VERSION 5.8 ;
BUSBITCHARS "[]" ;
DIVIDERCHAR "/" ;
UNITS
    DATABASE MICRONS 1000 ;
END UNITS

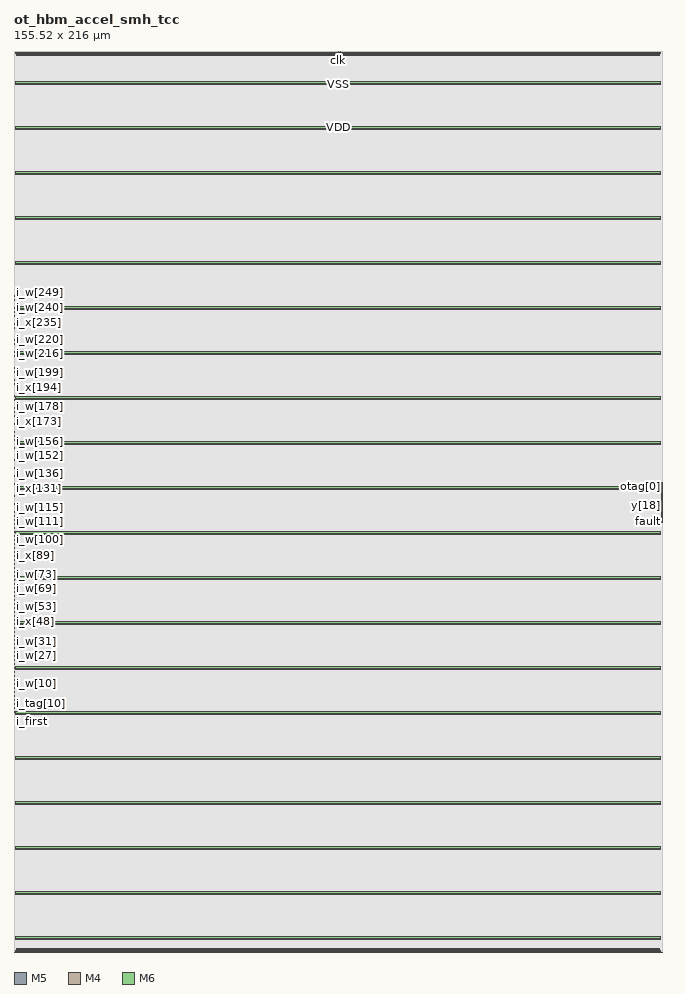
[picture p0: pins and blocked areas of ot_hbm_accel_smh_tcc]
MACRO ot_hbm_accel_smh_tcc
  FOREIGN ot_hbm_accel_smh_tcc 0 0 ;
  CLASS BLOCK ;
  SIZE 155.52 BY 216 ;
  PIN clk
    DIRECTION INPUT ;
    USE SIGNAL ;
    PORT
      LAYER M5 ;
        RECT  77.76 215.808 77.784 216 ;
    END
  END clk
  PIN fault
    DIRECTION OUTPUT ;
    USE SIGNAL ;
    PORT
      LAYER M4 ;
        RECT  155.328 103.392 155.52 103.416 ;
    END
  END fault
  PIN i_first
    DIRECTION INPUT ;
    USE SIGNAL ;
    PORT
      LAYER M4 ;
        RECT  0 57.216 0.192 57.24 ;
    END
  END i_first
  PIN i_last
    DIRECTION INPUT ;
    USE SIGNAL ;
    PORT
      LAYER M4 ;
        RECT  0 57.408 0.192 57.432 ;
    END
  END i_last
  PIN i_tag[0]
    DIRECTION INPUT ;
    USE SIGNAL ;
    PORT
      LAYER M4 ;
        RECT  0 57.6 0.192 57.624 ;
    END
  END i_tag[0]
  PIN i_tag[10]
    DIRECTION INPUT ;
    USE SIGNAL ;
    PORT
      LAYER M4 ;
        RECT  0 59.52 0.192 59.544 ;
    END
  END i_tag[10]
  PIN i_tag[11]
    DIRECTION INPUT ;
    USE SIGNAL ;
    PORT
      LAYER M4 ;
        RECT  0 59.712 0.192 59.736 ;
    END
  END i_tag[11]
  PIN i_tag[12]
    DIRECTION INPUT ;
    USE SIGNAL ;
    PORT
      LAYER M4 ;
        RECT  0 59.904 0.192 59.928 ;
    END
  END i_tag[12]
  PIN i_tag[13]
    DIRECTION INPUT ;
    USE SIGNAL ;
    PORT
      LAYER M4 ;
        RECT  0 60.096 0.192 60.12 ;
    END
  END i_tag[13]
  PIN i_tag[14]
    DIRECTION INPUT ;
    USE SIGNAL ;
    PORT
      LAYER M4 ;
        RECT  0 60.288 0.192 60.312 ;
    END
  END i_tag[14]
  PIN i_tag[15]
    DIRECTION INPUT ;
    USE SIGNAL ;
    PORT
      LAYER M4 ;
        RECT  0 60.48 0.192 60.504 ;
    END
  END i_tag[15]
  PIN i_tag[1]
    DIRECTION INPUT ;
    USE SIGNAL ;
    PORT
      LAYER M4 ;
        RECT  0 57.792 0.192 57.816 ;
    END
  END i_tag[1]
  PIN i_tag[2]
    DIRECTION INPUT ;
    USE SIGNAL ;
    PORT
      LAYER M4 ;
        RECT  0 57.984 0.192 58.008 ;
    END
  END i_tag[2]
  PIN i_tag[3]
    DIRECTION INPUT ;
    USE SIGNAL ;
    PORT
      LAYER M4 ;
        RECT  0 58.176 0.192 58.2 ;
    END
  END i_tag[3]
  PIN i_tag[4]
    DIRECTION INPUT ;
    USE SIGNAL ;
    PORT
      LAYER M4 ;
        RECT  0 58.368 0.192 58.392 ;
    END
  END i_tag[4]
  PIN i_tag[5]
    DIRECTION INPUT ;
    USE SIGNAL ;
    PORT
      LAYER M4 ;
        RECT  0 58.56 0.192 58.584 ;
    END
  END i_tag[5]
  PIN i_tag[6]
    DIRECTION INPUT ;
    USE SIGNAL ;
    PORT
      LAYER M4 ;
        RECT  0 58.752 0.192 58.776 ;
    END
  END i_tag[6]
  PIN i_tag[7]
    DIRECTION INPUT ;
    USE SIGNAL ;
    PORT
      LAYER M4 ;
        RECT  0 58.944 0.192 58.968 ;
    END
  END i_tag[7]
  PIN i_tag[8]
    DIRECTION INPUT ;
    USE SIGNAL ;
    PORT
      LAYER M4 ;
        RECT  0 59.136 0.192 59.16 ;
    END
  END i_tag[8]
  PIN i_tag[9]
    DIRECTION INPUT ;
    USE SIGNAL ;
    PORT
      LAYER M4 ;
        RECT  0 59.328 0.192 59.352 ;
    END
  END i_tag[9]
  PIN i_v
    DIRECTION INPUT ;
    USE SIGNAL ;
    PORT
      LAYER M4 ;
        RECT  0 57.024 0.192 57.048 ;
    END
  END i_v
  PIN i_w[0]
    DIRECTION INPUT ;
    USE SIGNAL ;
    PORT
      LAYER M4 ;
        RECT  0 60.672 0.192 60.696 ;
    END
  END i_w[0]
  PIN i_w[100]
    DIRECTION INPUT ;
    USE SIGNAL ;
    PORT
      LAYER M4 ;
        RECT  0 99.072 0.192 99.096 ;
    END
  END i_w[100]
  PIN i_w[101]
    DIRECTION INPUT ;
    USE SIGNAL ;
    PORT
      LAYER M4 ;
        RECT  0 99.456 0.192 99.48 ;
    END
  END i_w[101]
  PIN i_w[102]
    DIRECTION INPUT ;
    USE SIGNAL ;
    PORT
      LAYER M4 ;
        RECT  0 99.84 0.192 99.864 ;
    END
  END i_w[102]
  PIN i_w[103]
    DIRECTION INPUT ;
    USE SIGNAL ;
    PORT
      LAYER M4 ;
        RECT  0 100.224 0.192 100.248 ;
    END
  END i_w[103]
  PIN i_w[104]
    DIRECTION INPUT ;
    USE SIGNAL ;
    PORT
      LAYER M4 ;
        RECT  0 100.608 0.192 100.632 ;
    END
  END i_w[104]
  PIN i_w[105]
    DIRECTION INPUT ;
    USE SIGNAL ;
    PORT
      LAYER M4 ;
        RECT  0 100.992 0.192 101.016 ;
    END
  END i_w[105]
  PIN i_w[106]
    DIRECTION INPUT ;
    USE SIGNAL ;
    PORT
      LAYER M4 ;
        RECT  0 101.376 0.192 101.4 ;
    END
  END i_w[106]
  PIN i_w[107]
    DIRECTION INPUT ;
    USE SIGNAL ;
    PORT
      LAYER M4 ;
        RECT  0 101.76 0.192 101.784 ;
    END
  END i_w[107]
  PIN i_w[108]
    DIRECTION INPUT ;
    USE SIGNAL ;
    PORT
      LAYER M4 ;
        RECT  0 102.144 0.192 102.168 ;
    END
  END i_w[108]
  PIN i_w[109]
    DIRECTION INPUT ;
    USE SIGNAL ;
    PORT
      LAYER M4 ;
        RECT  0 102.528 0.192 102.552 ;
    END
  END i_w[109]
  PIN i_w[10]
    DIRECTION INPUT ;
    USE SIGNAL ;
    PORT
      LAYER M4 ;
        RECT  0 64.512 0.192 64.536 ;
    END
  END i_w[10]
  PIN i_w[110]
    DIRECTION INPUT ;
    USE SIGNAL ;
    PORT
      LAYER M4 ;
        RECT  0 102.912 0.192 102.936 ;
    END
  END i_w[110]
  PIN i_w[111]
    DIRECTION INPUT ;
    USE SIGNAL ;
    PORT
      LAYER M4 ;
        RECT  0 103.296 0.192 103.32 ;
    END
  END i_w[111]
  PIN i_w[112]
    DIRECTION INPUT ;
    USE SIGNAL ;
    PORT
      LAYER M4 ;
        RECT  0 103.68 0.192 103.704 ;
    END
  END i_w[112]
  PIN i_w[113]
    DIRECTION INPUT ;
    USE SIGNAL ;
    PORT
      LAYER M4 ;
        RECT  0 104.064 0.192 104.088 ;
    END
  END i_w[113]
  PIN i_w[114]
    DIRECTION INPUT ;
    USE SIGNAL ;
    PORT
      LAYER M4 ;
        RECT  0 104.448 0.192 104.472 ;
    END
  END i_w[114]
  PIN i_w[115]
    DIRECTION INPUT ;
    USE SIGNAL ;
    PORT
      LAYER M4 ;
        RECT  0 104.832 0.192 104.856 ;
    END
  END i_w[115]
  PIN i_w[116]
    DIRECTION INPUT ;
    USE SIGNAL ;
    PORT
      LAYER M4 ;
        RECT  0 105.216 0.192 105.24 ;
    END
  END i_w[116]
  PIN i_w[117]
    DIRECTION INPUT ;
    USE SIGNAL ;
    PORT
      LAYER M4 ;
        RECT  0 105.6 0.192 105.624 ;
    END
  END i_w[117]
  PIN i_w[118]
    DIRECTION INPUT ;
    USE SIGNAL ;
    PORT
      LAYER M4 ;
        RECT  0 105.984 0.192 106.008 ;
    END
  END i_w[118]
  PIN i_w[119]
    DIRECTION INPUT ;
    USE SIGNAL ;
    PORT
      LAYER M4 ;
        RECT  0 106.368 0.192 106.392 ;
    END
  END i_w[119]
  PIN i_w[11]
    DIRECTION INPUT ;
    USE SIGNAL ;
    PORT
      LAYER M4 ;
        RECT  0 64.896 0.192 64.92 ;
    END
  END i_w[11]
  PIN i_w[120]
    DIRECTION INPUT ;
    USE SIGNAL ;
    PORT
      LAYER M4 ;
        RECT  0 106.752 0.192 106.776 ;
    END
  END i_w[120]
  PIN i_w[121]
    DIRECTION INPUT ;
    USE SIGNAL ;
    PORT
      LAYER M4 ;
        RECT  0 107.136 0.192 107.16 ;
    END
  END i_w[121]
  PIN i_w[122]
    DIRECTION INPUT ;
    USE SIGNAL ;
    PORT
      LAYER M4 ;
        RECT  0 107.52 0.192 107.544 ;
    END
  END i_w[122]
  PIN i_w[123]
    DIRECTION INPUT ;
    USE SIGNAL ;
    PORT
      LAYER M4 ;
        RECT  0 107.904 0.192 107.928 ;
    END
  END i_w[123]
  PIN i_w[124]
    DIRECTION INPUT ;
    USE SIGNAL ;
    PORT
      LAYER M4 ;
        RECT  0 108.288 0.192 108.312 ;
    END
  END i_w[124]
  PIN i_w[125]
    DIRECTION INPUT ;
    USE SIGNAL ;
    PORT
      LAYER M4 ;
        RECT  0 108.672 0.192 108.696 ;
    END
  END i_w[125]
  PIN i_w[126]
    DIRECTION INPUT ;
    USE SIGNAL ;
    PORT
      LAYER M4 ;
        RECT  0 109.056 0.192 109.08 ;
    END
  END i_w[126]
  PIN i_w[127]
    DIRECTION INPUT ;
    USE SIGNAL ;
    PORT
      LAYER M4 ;
        RECT  0 109.44 0.192 109.464 ;
    END
  END i_w[127]
  PIN i_w[128]
    DIRECTION INPUT ;
    USE SIGNAL ;
    PORT
      LAYER M4 ;
        RECT  0 109.824 0.192 109.848 ;
    END
  END i_w[128]
  PIN i_w[129]
    DIRECTION INPUT ;
    USE SIGNAL ;
    PORT
      LAYER M4 ;
        RECT  0 110.208 0.192 110.232 ;
    END
  END i_w[129]
  PIN i_w[12]
    DIRECTION INPUT ;
    USE SIGNAL ;
    PORT
      LAYER M4 ;
        RECT  0 65.28 0.192 65.304 ;
    END
  END i_w[12]
  PIN i_w[130]
    DIRECTION INPUT ;
    USE SIGNAL ;
    PORT
      LAYER M4 ;
        RECT  0 110.592 0.192 110.616 ;
    END
  END i_w[130]
  PIN i_w[131]
    DIRECTION INPUT ;
    USE SIGNAL ;
    PORT
      LAYER M4 ;
        RECT  0 110.976 0.192 111 ;
    END
  END i_w[131]
  PIN i_w[132]
    DIRECTION INPUT ;
    USE SIGNAL ;
    PORT
      LAYER M4 ;
        RECT  0 111.36 0.192 111.384 ;
    END
  END i_w[132]
  PIN i_w[133]
    DIRECTION INPUT ;
    USE SIGNAL ;
    PORT
      LAYER M4 ;
        RECT  0 111.744 0.192 111.768 ;
    END
  END i_w[133]
  PIN i_w[134]
    DIRECTION INPUT ;
    USE SIGNAL ;
    PORT
      LAYER M4 ;
        RECT  0 112.128 0.192 112.152 ;
    END
  END i_w[134]
  PIN i_w[135]
    DIRECTION INPUT ;
    USE SIGNAL ;
    PORT
      LAYER M4 ;
        RECT  0 112.512 0.192 112.536 ;
    END
  END i_w[135]
  PIN i_w[136]
    DIRECTION INPUT ;
    USE SIGNAL ;
    PORT
      LAYER M4 ;
        RECT  0 112.896 0.192 112.92 ;
    END
  END i_w[136]
  PIN i_w[137]
    DIRECTION INPUT ;
    USE SIGNAL ;
    PORT
      LAYER M4 ;
        RECT  0 113.28 0.192 113.304 ;
    END
  END i_w[137]
  PIN i_w[138]
    DIRECTION INPUT ;
    USE SIGNAL ;
    PORT
      LAYER M4 ;
        RECT  0 113.664 0.192 113.688 ;
    END
  END i_w[138]
  PIN i_w[139]
    DIRECTION INPUT ;
    USE SIGNAL ;
    PORT
      LAYER M4 ;
        RECT  0 114.048 0.192 114.072 ;
    END
  END i_w[139]
  PIN i_w[13]
    DIRECTION INPUT ;
    USE SIGNAL ;
    PORT
      LAYER M4 ;
        RECT  0 65.664 0.192 65.688 ;
    END
  END i_w[13]
  PIN i_w[140]
    DIRECTION INPUT ;
    USE SIGNAL ;
    PORT
      LAYER M4 ;
        RECT  0 114.432 0.192 114.456 ;
    END
  END i_w[140]
  PIN i_w[141]
    DIRECTION INPUT ;
    USE SIGNAL ;
    PORT
      LAYER M4 ;
        RECT  0 114.816 0.192 114.84 ;
    END
  END i_w[141]
  PIN i_w[142]
    DIRECTION INPUT ;
    USE SIGNAL ;
    PORT
      LAYER M4 ;
        RECT  0 115.2 0.192 115.224 ;
    END
  END i_w[142]
  PIN i_w[143]
    DIRECTION INPUT ;
    USE SIGNAL ;
    PORT
      LAYER M4 ;
        RECT  0 115.584 0.192 115.608 ;
    END
  END i_w[143]
  PIN i_w[144]
    DIRECTION INPUT ;
    USE SIGNAL ;
    PORT
      LAYER M4 ;
        RECT  0 115.968 0.192 115.992 ;
    END
  END i_w[144]
  PIN i_w[145]
    DIRECTION INPUT ;
    USE SIGNAL ;
    PORT
      LAYER M4 ;
        RECT  0 116.352 0.192 116.376 ;
    END
  END i_w[145]
  PIN i_w[146]
    DIRECTION INPUT ;
    USE SIGNAL ;
    PORT
      LAYER M4 ;
        RECT  0 116.736 0.192 116.76 ;
    END
  END i_w[146]
  PIN i_w[147]
    DIRECTION INPUT ;
    USE SIGNAL ;
    PORT
      LAYER M4 ;
        RECT  0 117.12 0.192 117.144 ;
    END
  END i_w[147]
  PIN i_w[148]
    DIRECTION INPUT ;
    USE SIGNAL ;
    PORT
      LAYER M4 ;
        RECT  0 117.504 0.192 117.528 ;
    END
  END i_w[148]
  PIN i_w[149]
    DIRECTION INPUT ;
    USE SIGNAL ;
    PORT
      LAYER M4 ;
        RECT  0 117.888 0.192 117.912 ;
    END
  END i_w[149]
  PIN i_w[14]
    DIRECTION INPUT ;
    USE SIGNAL ;
    PORT
      LAYER M4 ;
        RECT  0 66.048 0.192 66.072 ;
    END
  END i_w[14]
  PIN i_w[150]
    DIRECTION INPUT ;
    USE SIGNAL ;
    PORT
      LAYER M4 ;
        RECT  0 118.272 0.192 118.296 ;
    END
  END i_w[150]
  PIN i_w[151]
    DIRECTION INPUT ;
    USE SIGNAL ;
    PORT
      LAYER M4 ;
        RECT  0 118.656 0.192 118.68 ;
    END
  END i_w[151]
  PIN i_w[152]
    DIRECTION INPUT ;
    USE SIGNAL ;
    PORT
      LAYER M4 ;
        RECT  0 119.04 0.192 119.064 ;
    END
  END i_w[152]
  PIN i_w[153]
    DIRECTION INPUT ;
    USE SIGNAL ;
    PORT
      LAYER M4 ;
        RECT  0 119.424 0.192 119.448 ;
    END
  END i_w[153]
  PIN i_w[154]
    DIRECTION INPUT ;
    USE SIGNAL ;
    PORT
      LAYER M4 ;
        RECT  0 119.808 0.192 119.832 ;
    END
  END i_w[154]
  PIN i_w[155]
    DIRECTION INPUT ;
    USE SIGNAL ;
    PORT
      LAYER M4 ;
        RECT  0 120.192 0.192 120.216 ;
    END
  END i_w[155]
  PIN i_w[156]
    DIRECTION INPUT ;
    USE SIGNAL ;
    PORT
      LAYER M4 ;
        RECT  0 120.576 0.192 120.6 ;
    END
  END i_w[156]
  PIN i_w[157]
    DIRECTION INPUT ;
    USE SIGNAL ;
    PORT
      LAYER M4 ;
        RECT  0 120.96 0.192 120.984 ;
    END
  END i_w[157]
  PIN i_w[158]
    DIRECTION INPUT ;
    USE SIGNAL ;
    PORT
      LAYER M4 ;
        RECT  0 121.344 0.192 121.368 ;
    END
  END i_w[158]
  PIN i_w[159]
    DIRECTION INPUT ;
    USE SIGNAL ;
    PORT
      LAYER M4 ;
        RECT  0 121.728 0.192 121.752 ;
    END
  END i_w[159]
  PIN i_w[15]
    DIRECTION INPUT ;
    USE SIGNAL ;
    PORT
      LAYER M4 ;
        RECT  0 66.432 0.192 66.456 ;
    END
  END i_w[15]
  PIN i_w[160]
    DIRECTION INPUT ;
    USE SIGNAL ;
    PORT
      LAYER M4 ;
        RECT  0 122.112 0.192 122.136 ;
    END
  END i_w[160]
  PIN i_w[161]
    DIRECTION INPUT ;
    USE SIGNAL ;
    PORT
      LAYER M4 ;
        RECT  0 122.496 0.192 122.52 ;
    END
  END i_w[161]
  PIN i_w[162]
    DIRECTION INPUT ;
    USE SIGNAL ;
    PORT
      LAYER M4 ;
        RECT  0 122.88 0.192 122.904 ;
    END
  END i_w[162]
  PIN i_w[163]
    DIRECTION INPUT ;
    USE SIGNAL ;
    PORT
      LAYER M4 ;
        RECT  0 123.264 0.192 123.288 ;
    END
  END i_w[163]
  PIN i_w[164]
    DIRECTION INPUT ;
    USE SIGNAL ;
    PORT
      LAYER M4 ;
        RECT  0 123.648 0.192 123.672 ;
    END
  END i_w[164]
  PIN i_w[165]
    DIRECTION INPUT ;
    USE SIGNAL ;
    PORT
      LAYER M4 ;
        RECT  0 124.032 0.192 124.056 ;
    END
  END i_w[165]
  PIN i_w[166]
    DIRECTION INPUT ;
    USE SIGNAL ;
    PORT
      LAYER M4 ;
        RECT  0 124.416 0.192 124.44 ;
    END
  END i_w[166]
  PIN i_w[167]
    DIRECTION INPUT ;
    USE SIGNAL ;
    PORT
      LAYER M4 ;
        RECT  0 124.8 0.192 124.824 ;
    END
  END i_w[167]
  PIN i_w[168]
    DIRECTION INPUT ;
    USE SIGNAL ;
    PORT
      LAYER M4 ;
        RECT  0 125.184 0.192 125.208 ;
    END
  END i_w[168]
  PIN i_w[169]
    DIRECTION INPUT ;
    USE SIGNAL ;
    PORT
      LAYER M4 ;
        RECT  0 125.568 0.192 125.592 ;
    END
  END i_w[169]
  PIN i_w[16]
    DIRECTION INPUT ;
    USE SIGNAL ;
    PORT
      LAYER M4 ;
        RECT  0 66.816 0.192 66.84 ;
    END
  END i_w[16]
  PIN i_w[170]
    DIRECTION INPUT ;
    USE SIGNAL ;
    PORT
      LAYER M4 ;
        RECT  0 125.952 0.192 125.976 ;
    END
  END i_w[170]
  PIN i_w[171]
    DIRECTION INPUT ;
    USE SIGNAL ;
    PORT
      LAYER M4 ;
        RECT  0 126.336 0.192 126.36 ;
    END
  END i_w[171]
  PIN i_w[172]
    DIRECTION INPUT ;
    USE SIGNAL ;
    PORT
      LAYER M4 ;
        RECT  0 126.72 0.192 126.744 ;
    END
  END i_w[172]
  PIN i_w[173]
    DIRECTION INPUT ;
    USE SIGNAL ;
    PORT
      LAYER M4 ;
        RECT  0 127.104 0.192 127.128 ;
    END
  END i_w[173]
  PIN i_w[174]
    DIRECTION INPUT ;
    USE SIGNAL ;
    PORT
      LAYER M4 ;
        RECT  0 127.488 0.192 127.512 ;
    END
  END i_w[174]
  PIN i_w[175]
    DIRECTION INPUT ;
    USE SIGNAL ;
    PORT
      LAYER M4 ;
        RECT  0 127.872 0.192 127.896 ;
    END
  END i_w[175]
  PIN i_w[176]
    DIRECTION INPUT ;
    USE SIGNAL ;
    PORT
      LAYER M4 ;
        RECT  0 128.256 0.192 128.28 ;
    END
  END i_w[176]
  PIN i_w[177]
    DIRECTION INPUT ;
    USE SIGNAL ;
    PORT
      LAYER M4 ;
        RECT  0 128.64 0.192 128.664 ;
    END
  END i_w[177]
  PIN i_w[178]
    DIRECTION INPUT ;
    USE SIGNAL ;
    PORT
      LAYER M4 ;
        RECT  0 129.024 0.192 129.048 ;
    END
  END i_w[178]
  PIN i_w[179]
    DIRECTION INPUT ;
    USE SIGNAL ;
    PORT
      LAYER M4 ;
        RECT  0 129.408 0.192 129.432 ;
    END
  END i_w[179]
  PIN i_w[17]
    DIRECTION INPUT ;
    USE SIGNAL ;
    PORT
      LAYER M4 ;
        RECT  0 67.2 0.192 67.224 ;
    END
  END i_w[17]
  PIN i_w[180]
    DIRECTION INPUT ;
    USE SIGNAL ;
    PORT
      LAYER M4 ;
        RECT  0 129.792 0.192 129.816 ;
    END
  END i_w[180]
  PIN i_w[181]
    DIRECTION INPUT ;
    USE SIGNAL ;
    PORT
      LAYER M4 ;
        RECT  0 130.176 0.192 130.2 ;
    END
  END i_w[181]
  PIN i_w[182]
    DIRECTION INPUT ;
    USE SIGNAL ;
    PORT
      LAYER M4 ;
        RECT  0 130.56 0.192 130.584 ;
    END
  END i_w[182]
  PIN i_w[183]
    DIRECTION INPUT ;
    USE SIGNAL ;
    PORT
      LAYER M4 ;
        RECT  0 130.944 0.192 130.968 ;
    END
  END i_w[183]
  PIN i_w[184]
    DIRECTION INPUT ;
    USE SIGNAL ;
    PORT
      LAYER M4 ;
        RECT  0 131.328 0.192 131.352 ;
    END
  END i_w[184]
  PIN i_w[185]
    DIRECTION INPUT ;
    USE SIGNAL ;
    PORT
      LAYER M4 ;
        RECT  0 131.712 0.192 131.736 ;
    END
  END i_w[185]
  PIN i_w[186]
    DIRECTION INPUT ;
    USE SIGNAL ;
    PORT
      LAYER M4 ;
        RECT  0 132.096 0.192 132.12 ;
    END
  END i_w[186]
  PIN i_w[187]
    DIRECTION INPUT ;
    USE SIGNAL ;
    PORT
      LAYER M4 ;
        RECT  0 132.48 0.192 132.504 ;
    END
  END i_w[187]
  PIN i_w[188]
    DIRECTION INPUT ;
    USE SIGNAL ;
    PORT
      LAYER M4 ;
        RECT  0 132.864 0.192 132.888 ;
    END
  END i_w[188]
  PIN i_w[189]
    DIRECTION INPUT ;
    USE SIGNAL ;
    PORT
      LAYER M4 ;
        RECT  0 133.248 0.192 133.272 ;
    END
  END i_w[189]
  PIN i_w[18]
    DIRECTION INPUT ;
    USE SIGNAL ;
    PORT
      LAYER M4 ;
        RECT  0 67.584 0.192 67.608 ;
    END
  END i_w[18]
  PIN i_w[190]
    DIRECTION INPUT ;
    USE SIGNAL ;
    PORT
      LAYER M4 ;
        RECT  0 133.632 0.192 133.656 ;
    END
  END i_w[190]
  PIN i_w[191]
    DIRECTION INPUT ;
    USE SIGNAL ;
    PORT
      LAYER M4 ;
        RECT  0 134.016 0.192 134.04 ;
    END
  END i_w[191]
  PIN i_w[192]
    DIRECTION INPUT ;
    USE SIGNAL ;
    PORT
      LAYER M4 ;
        RECT  0 134.4 0.192 134.424 ;
    END
  END i_w[192]
  PIN i_w[193]
    DIRECTION INPUT ;
    USE SIGNAL ;
    PORT
      LAYER M4 ;
        RECT  0 134.784 0.192 134.808 ;
    END
  END i_w[193]
  PIN i_w[194]
    DIRECTION INPUT ;
    USE SIGNAL ;
    PORT
      LAYER M4 ;
        RECT  0 135.168 0.192 135.192 ;
    END
  END i_w[194]
  PIN i_w[195]
    DIRECTION INPUT ;
    USE SIGNAL ;
    PORT
      LAYER M4 ;
        RECT  0 135.552 0.192 135.576 ;
    END
  END i_w[195]
  PIN i_w[196]
    DIRECTION INPUT ;
    USE SIGNAL ;
    PORT
      LAYER M4 ;
        RECT  0 135.936 0.192 135.96 ;
    END
  END i_w[196]
  PIN i_w[197]
    DIRECTION INPUT ;
    USE SIGNAL ;
    PORT
      LAYER M4 ;
        RECT  0 136.32 0.192 136.344 ;
    END
  END i_w[197]
  PIN i_w[198]
    DIRECTION INPUT ;
    USE SIGNAL ;
    PORT
      LAYER M4 ;
        RECT  0 136.704 0.192 136.728 ;
    END
  END i_w[198]
  PIN i_w[199]
    DIRECTION INPUT ;
    USE SIGNAL ;
    PORT
      LAYER M4 ;
        RECT  0 137.088 0.192 137.112 ;
    END
  END i_w[199]
  PIN i_w[19]
    DIRECTION INPUT ;
    USE SIGNAL ;
    PORT
      LAYER M4 ;
        RECT  0 67.968 0.192 67.992 ;
    END
  END i_w[19]
  PIN i_w[1]
    DIRECTION INPUT ;
    USE SIGNAL ;
    PORT
      LAYER M4 ;
        RECT  0 61.056 0.192 61.08 ;
    END
  END i_w[1]
  PIN i_w[200]
    DIRECTION INPUT ;
    USE SIGNAL ;
    PORT
      LAYER M4 ;
        RECT  0 137.472 0.192 137.496 ;
    END
  END i_w[200]
  PIN i_w[201]
    DIRECTION INPUT ;
    USE SIGNAL ;
    PORT
      LAYER M4 ;
        RECT  0 137.856 0.192 137.88 ;
    END
  END i_w[201]
  PIN i_w[202]
    DIRECTION INPUT ;
    USE SIGNAL ;
    PORT
      LAYER M4 ;
        RECT  0 138.24 0.192 138.264 ;
    END
  END i_w[202]
  PIN i_w[203]
    DIRECTION INPUT ;
    USE SIGNAL ;
    PORT
      LAYER M4 ;
        RECT  0 138.624 0.192 138.648 ;
    END
  END i_w[203]
  PIN i_w[204]
    DIRECTION INPUT ;
    USE SIGNAL ;
    PORT
      LAYER M4 ;
        RECT  0 139.008 0.192 139.032 ;
    END
  END i_w[204]
  PIN i_w[205]
    DIRECTION INPUT ;
    USE SIGNAL ;
    PORT
      LAYER M4 ;
        RECT  0 139.392 0.192 139.416 ;
    END
  END i_w[205]
  PIN i_w[206]
    DIRECTION INPUT ;
    USE SIGNAL ;
    PORT
      LAYER M4 ;
        RECT  0 139.776 0.192 139.8 ;
    END
  END i_w[206]
  PIN i_w[207]
    DIRECTION INPUT ;
    USE SIGNAL ;
    PORT
      LAYER M4 ;
        RECT  0 140.16 0.192 140.184 ;
    END
  END i_w[207]
  PIN i_w[208]
    DIRECTION INPUT ;
    USE SIGNAL ;
    PORT
      LAYER M4 ;
        RECT  0 140.544 0.192 140.568 ;
    END
  END i_w[208]
  PIN i_w[209]
    DIRECTION INPUT ;
    USE SIGNAL ;
    PORT
      LAYER M4 ;
        RECT  0 140.928 0.192 140.952 ;
    END
  END i_w[209]
  PIN i_w[20]
    DIRECTION INPUT ;
    USE SIGNAL ;
    PORT
      LAYER M4 ;
        RECT  0 68.352 0.192 68.376 ;
    END
  END i_w[20]
  PIN i_w[210]
    DIRECTION INPUT ;
    USE SIGNAL ;
    PORT
      LAYER M4 ;
        RECT  0 141.312 0.192 141.336 ;
    END
  END i_w[210]
  PIN i_w[211]
    DIRECTION INPUT ;
    USE SIGNAL ;
    PORT
      LAYER M4 ;
        RECT  0 141.696 0.192 141.72 ;
    END
  END i_w[211]
  PIN i_w[212]
    DIRECTION INPUT ;
    USE SIGNAL ;
    PORT
      LAYER M4 ;
        RECT  0 142.08 0.192 142.104 ;
    END
  END i_w[212]
  PIN i_w[213]
    DIRECTION INPUT ;
    USE SIGNAL ;
    PORT
      LAYER M4 ;
        RECT  0 142.464 0.192 142.488 ;
    END
  END i_w[213]
  PIN i_w[214]
    DIRECTION INPUT ;
    USE SIGNAL ;
    PORT
      LAYER M4 ;
        RECT  0 142.848 0.192 142.872 ;
    END
  END i_w[214]
  PIN i_w[215]
    DIRECTION INPUT ;
    USE SIGNAL ;
    PORT
      LAYER M4 ;
        RECT  0 143.232 0.192 143.256 ;
    END
  END i_w[215]
  PIN i_w[216]
    DIRECTION INPUT ;
    USE SIGNAL ;
    PORT
      LAYER M4 ;
        RECT  0 143.616 0.192 143.64 ;
    END
  END i_w[216]
  PIN i_w[217]
    DIRECTION INPUT ;
    USE SIGNAL ;
    PORT
      LAYER M4 ;
        RECT  0 144 0.192 144.024 ;
    END
  END i_w[217]
  PIN i_w[218]
    DIRECTION INPUT ;
    USE SIGNAL ;
    PORT
      LAYER M4 ;
        RECT  0 144.384 0.192 144.408 ;
    END
  END i_w[218]
  PIN i_w[219]
    DIRECTION INPUT ;
    USE SIGNAL ;
    PORT
      LAYER M4 ;
        RECT  0 144.768 0.192 144.792 ;
    END
  END i_w[219]
  PIN i_w[21]
    DIRECTION INPUT ;
    USE SIGNAL ;
    PORT
      LAYER M4 ;
        RECT  0 68.736 0.192 68.76 ;
    END
  END i_w[21]
  PIN i_w[220]
    DIRECTION INPUT ;
    USE SIGNAL ;
    PORT
      LAYER M4 ;
        RECT  0 145.152 0.192 145.176 ;
    END
  END i_w[220]
  PIN i_w[221]
    DIRECTION INPUT ;
    USE SIGNAL ;
    PORT
      LAYER M4 ;
        RECT  0 145.536 0.192 145.56 ;
    END
  END i_w[221]
  PIN i_w[222]
    DIRECTION INPUT ;
    USE SIGNAL ;
    PORT
      LAYER M4 ;
        RECT  0 145.92 0.192 145.944 ;
    END
  END i_w[222]
  PIN i_w[223]
    DIRECTION INPUT ;
    USE SIGNAL ;
    PORT
      LAYER M4 ;
        RECT  0 146.304 0.192 146.328 ;
    END
  END i_w[223]
  PIN i_w[224]
    DIRECTION INPUT ;
    USE SIGNAL ;
    PORT
      LAYER M4 ;
        RECT  0 146.688 0.192 146.712 ;
    END
  END i_w[224]
  PIN i_w[225]
    DIRECTION INPUT ;
    USE SIGNAL ;
    PORT
      LAYER M4 ;
        RECT  0 147.072 0.192 147.096 ;
    END
  END i_w[225]
  PIN i_w[226]
    DIRECTION INPUT ;
    USE SIGNAL ;
    PORT
      LAYER M4 ;
        RECT  0 147.456 0.192 147.48 ;
    END
  END i_w[226]
  PIN i_w[227]
    DIRECTION INPUT ;
    USE SIGNAL ;
    PORT
      LAYER M4 ;
        RECT  0 147.84 0.192 147.864 ;
    END
  END i_w[227]
  PIN i_w[228]
    DIRECTION INPUT ;
    USE SIGNAL ;
    PORT
      LAYER M4 ;
        RECT  0 148.224 0.192 148.248 ;
    END
  END i_w[228]
  PIN i_w[229]
    DIRECTION INPUT ;
    USE SIGNAL ;
    PORT
      LAYER M4 ;
        RECT  0 148.608 0.192 148.632 ;
    END
  END i_w[229]
  PIN i_w[22]
    DIRECTION INPUT ;
    USE SIGNAL ;
    PORT
      LAYER M4 ;
        RECT  0 69.12 0.192 69.144 ;
    END
  END i_w[22]
  PIN i_w[230]
    DIRECTION INPUT ;
    USE SIGNAL ;
    PORT
      LAYER M4 ;
        RECT  0 148.992 0.192 149.016 ;
    END
  END i_w[230]
  PIN i_w[231]
    DIRECTION INPUT ;
    USE SIGNAL ;
    PORT
      LAYER M4 ;
        RECT  0 149.376 0.192 149.4 ;
    END
  END i_w[231]
  PIN i_w[232]
    DIRECTION INPUT ;
    USE SIGNAL ;
    PORT
      LAYER M4 ;
        RECT  0 149.76 0.192 149.784 ;
    END
  END i_w[232]
  PIN i_w[233]
    DIRECTION INPUT ;
    USE SIGNAL ;
    PORT
      LAYER M4 ;
        RECT  0 150.144 0.192 150.168 ;
    END
  END i_w[233]
  PIN i_w[234]
    DIRECTION INPUT ;
    USE SIGNAL ;
    PORT
      LAYER M4 ;
        RECT  0 150.528 0.192 150.552 ;
    END
  END i_w[234]
  PIN i_w[235]
    DIRECTION INPUT ;
    USE SIGNAL ;
    PORT
      LAYER M4 ;
        RECT  0 150.912 0.192 150.936 ;
    END
  END i_w[235]
  PIN i_w[236]
    DIRECTION INPUT ;
    USE SIGNAL ;
    PORT
      LAYER M4 ;
        RECT  0 151.296 0.192 151.32 ;
    END
  END i_w[236]
  PIN i_w[237]
    DIRECTION INPUT ;
    USE SIGNAL ;
    PORT
      LAYER M4 ;
        RECT  0 151.68 0.192 151.704 ;
    END
  END i_w[237]
  PIN i_w[238]
    DIRECTION INPUT ;
    USE SIGNAL ;
    PORT
      LAYER M4 ;
        RECT  0 152.064 0.192 152.088 ;
    END
  END i_w[238]
  PIN i_w[239]
    DIRECTION INPUT ;
    USE SIGNAL ;
    PORT
      LAYER M4 ;
        RECT  0 152.448 0.192 152.472 ;
    END
  END i_w[239]
  PIN i_w[23]
    DIRECTION INPUT ;
    USE SIGNAL ;
    PORT
      LAYER M4 ;
        RECT  0 69.504 0.192 69.528 ;
    END
  END i_w[23]
  PIN i_w[240]
    DIRECTION INPUT ;
    USE SIGNAL ;
    PORT
      LAYER M4 ;
        RECT  0 152.832 0.192 152.856 ;
    END
  END i_w[240]
  PIN i_w[241]
    DIRECTION INPUT ;
    USE SIGNAL ;
    PORT
      LAYER M4 ;
        RECT  0 153.216 0.192 153.24 ;
    END
  END i_w[241]
  PIN i_w[242]
    DIRECTION INPUT ;
    USE SIGNAL ;
    PORT
      LAYER M4 ;
        RECT  0 153.6 0.192 153.624 ;
    END
  END i_w[242]
  PIN i_w[243]
    DIRECTION INPUT ;
    USE SIGNAL ;
    PORT
      LAYER M4 ;
        RECT  0 153.984 0.192 154.008 ;
    END
  END i_w[243]
  PIN i_w[244]
    DIRECTION INPUT ;
    USE SIGNAL ;
    PORT
      LAYER M4 ;
        RECT  0 154.368 0.192 154.392 ;
    END
  END i_w[244]
  PIN i_w[245]
    DIRECTION INPUT ;
    USE SIGNAL ;
    PORT
      LAYER M4 ;
        RECT  0 154.752 0.192 154.776 ;
    END
  END i_w[245]
  PIN i_w[246]
    DIRECTION INPUT ;
    USE SIGNAL ;
    PORT
      LAYER M4 ;
        RECT  0 155.136 0.192 155.16 ;
    END
  END i_w[246]
  PIN i_w[247]
    DIRECTION INPUT ;
    USE SIGNAL ;
    PORT
      LAYER M4 ;
        RECT  0 155.52 0.192 155.544 ;
    END
  END i_w[247]
  PIN i_w[248]
    DIRECTION INPUT ;
    USE SIGNAL ;
    PORT
      LAYER M4 ;
        RECT  0 155.904 0.192 155.928 ;
    END
  END i_w[248]
  PIN i_w[249]
    DIRECTION INPUT ;
    USE SIGNAL ;
    PORT
      LAYER M4 ;
        RECT  0 156.288 0.192 156.312 ;
    END
  END i_w[249]
  PIN i_w[24]
    DIRECTION INPUT ;
    USE SIGNAL ;
    PORT
      LAYER M4 ;
        RECT  0 69.888 0.192 69.912 ;
    END
  END i_w[24]
  PIN i_w[250]
    DIRECTION INPUT ;
    USE SIGNAL ;
    PORT
      LAYER M4 ;
        RECT  0 156.672 0.192 156.696 ;
    END
  END i_w[250]
  PIN i_w[251]
    DIRECTION INPUT ;
    USE SIGNAL ;
    PORT
      LAYER M4 ;
        RECT  0 157.056 0.192 157.08 ;
    END
  END i_w[251]
  PIN i_w[252]
    DIRECTION INPUT ;
    USE SIGNAL ;
    PORT
      LAYER M4 ;
        RECT  0 157.44 0.192 157.464 ;
    END
  END i_w[252]
  PIN i_w[253]
    DIRECTION INPUT ;
    USE SIGNAL ;
    PORT
      LAYER M4 ;
        RECT  0 157.824 0.192 157.848 ;
    END
  END i_w[253]
  PIN i_w[254]
    DIRECTION INPUT ;
    USE SIGNAL ;
    PORT
      LAYER M4 ;
        RECT  0 158.208 0.192 158.232 ;
    END
  END i_w[254]
  PIN i_w[255]
    DIRECTION INPUT ;
    USE SIGNAL ;
    PORT
      LAYER M4 ;
        RECT  0 158.592 0.192 158.616 ;
    END
  END i_w[255]
  PIN i_w[25]
    DIRECTION INPUT ;
    USE SIGNAL ;
    PORT
      LAYER M4 ;
        RECT  0 70.272 0.192 70.296 ;
    END
  END i_w[25]
  PIN i_w[26]
    DIRECTION INPUT ;
    USE SIGNAL ;
    PORT
      LAYER M4 ;
        RECT  0 70.656 0.192 70.68 ;
    END
  END i_w[26]
  PIN i_w[27]
    DIRECTION INPUT ;
    USE SIGNAL ;
    PORT
      LAYER M4 ;
        RECT  0 71.04 0.192 71.064 ;
    END
  END i_w[27]
  PIN i_w[28]
    DIRECTION INPUT ;
    USE SIGNAL ;
    PORT
      LAYER M4 ;
        RECT  0 71.424 0.192 71.448 ;
    END
  END i_w[28]
  PIN i_w[29]
    DIRECTION INPUT ;
    USE SIGNAL ;
    PORT
      LAYER M4 ;
        RECT  0 71.808 0.192 71.832 ;
    END
  END i_w[29]
  PIN i_w[2]
    DIRECTION INPUT ;
    USE SIGNAL ;
    PORT
      LAYER M4 ;
        RECT  0 61.44 0.192 61.464 ;
    END
  END i_w[2]
  PIN i_w[30]
    DIRECTION INPUT ;
    USE SIGNAL ;
    PORT
      LAYER M4 ;
        RECT  0 72.192 0.192 72.216 ;
    END
  END i_w[30]
  PIN i_w[31]
    DIRECTION INPUT ;
    USE SIGNAL ;
    PORT
      LAYER M4 ;
        RECT  0 72.576 0.192 72.6 ;
    END
  END i_w[31]
  PIN i_w[32]
    DIRECTION INPUT ;
    USE SIGNAL ;
    PORT
      LAYER M4 ;
        RECT  0 72.96 0.192 72.984 ;
    END
  END i_w[32]
  PIN i_w[33]
    DIRECTION INPUT ;
    USE SIGNAL ;
    PORT
      LAYER M4 ;
        RECT  0 73.344 0.192 73.368 ;
    END
  END i_w[33]
  PIN i_w[34]
    DIRECTION INPUT ;
    USE SIGNAL ;
    PORT
      LAYER M4 ;
        RECT  0 73.728 0.192 73.752 ;
    END
  END i_w[34]
  PIN i_w[35]
    DIRECTION INPUT ;
    USE SIGNAL ;
    PORT
      LAYER M4 ;
        RECT  0 74.112 0.192 74.136 ;
    END
  END i_w[35]
  PIN i_w[36]
    DIRECTION INPUT ;
    USE SIGNAL ;
    PORT
      LAYER M4 ;
        RECT  0 74.496 0.192 74.52 ;
    END
  END i_w[36]
  PIN i_w[37]
    DIRECTION INPUT ;
    USE SIGNAL ;
    PORT
      LAYER M4 ;
        RECT  0 74.88 0.192 74.904 ;
    END
  END i_w[37]
  PIN i_w[38]
    DIRECTION INPUT ;
    USE SIGNAL ;
    PORT
      LAYER M4 ;
        RECT  0 75.264 0.192 75.288 ;
    END
  END i_w[38]
  PIN i_w[39]
    DIRECTION INPUT ;
    USE SIGNAL ;
    PORT
      LAYER M4 ;
        RECT  0 75.648 0.192 75.672 ;
    END
  END i_w[39]
  PIN i_w[3]
    DIRECTION INPUT ;
    USE SIGNAL ;
    PORT
      LAYER M4 ;
        RECT  0 61.824 0.192 61.848 ;
    END
  END i_w[3]
  PIN i_w[40]
    DIRECTION INPUT ;
    USE SIGNAL ;
    PORT
      LAYER M4 ;
        RECT  0 76.032 0.192 76.056 ;
    END
  END i_w[40]
  PIN i_w[41]
    DIRECTION INPUT ;
    USE SIGNAL ;
    PORT
      LAYER M4 ;
        RECT  0 76.416 0.192 76.44 ;
    END
  END i_w[41]
  PIN i_w[42]
    DIRECTION INPUT ;
    USE SIGNAL ;
    PORT
      LAYER M4 ;
        RECT  0 76.8 0.192 76.824 ;
    END
  END i_w[42]
  PIN i_w[43]
    DIRECTION INPUT ;
    USE SIGNAL ;
    PORT
      LAYER M4 ;
        RECT  0 77.184 0.192 77.208 ;
    END
  END i_w[43]
  PIN i_w[44]
    DIRECTION INPUT ;
    USE SIGNAL ;
    PORT
      LAYER M4 ;
        RECT  0 77.568 0.192 77.592 ;
    END
  END i_w[44]
  PIN i_w[45]
    DIRECTION INPUT ;
    USE SIGNAL ;
    PORT
      LAYER M4 ;
        RECT  0 77.952 0.192 77.976 ;
    END
  END i_w[45]
  PIN i_w[46]
    DIRECTION INPUT ;
    USE SIGNAL ;
    PORT
      LAYER M4 ;
        RECT  0 78.336 0.192 78.36 ;
    END
  END i_w[46]
  PIN i_w[47]
    DIRECTION INPUT ;
    USE SIGNAL ;
    PORT
      LAYER M4 ;
        RECT  0 78.72 0.192 78.744 ;
    END
  END i_w[47]
  PIN i_w[48]
    DIRECTION INPUT ;
    USE SIGNAL ;
    PORT
      LAYER M4 ;
        RECT  0 79.104 0.192 79.128 ;
    END
  END i_w[48]
  PIN i_w[49]
    DIRECTION INPUT ;
    USE SIGNAL ;
    PORT
      LAYER M4 ;
        RECT  0 79.488 0.192 79.512 ;
    END
  END i_w[49]
  PIN i_w[4]
    DIRECTION INPUT ;
    USE SIGNAL ;
    PORT
      LAYER M4 ;
        RECT  0 62.208 0.192 62.232 ;
    END
  END i_w[4]
  PIN i_w[50]
    DIRECTION INPUT ;
    USE SIGNAL ;
    PORT
      LAYER M4 ;
        RECT  0 79.872 0.192 79.896 ;
    END
  END i_w[50]
  PIN i_w[51]
    DIRECTION INPUT ;
    USE SIGNAL ;
    PORT
      LAYER M4 ;
        RECT  0 80.256 0.192 80.28 ;
    END
  END i_w[51]
  PIN i_w[52]
    DIRECTION INPUT ;
    USE SIGNAL ;
    PORT
      LAYER M4 ;
        RECT  0 80.64 0.192 80.664 ;
    END
  END i_w[52]
  PIN i_w[53]
    DIRECTION INPUT ;
    USE SIGNAL ;
    PORT
      LAYER M4 ;
        RECT  0 81.024 0.192 81.048 ;
    END
  END i_w[53]
  PIN i_w[54]
    DIRECTION INPUT ;
    USE SIGNAL ;
    PORT
      LAYER M4 ;
        RECT  0 81.408 0.192 81.432 ;
    END
  END i_w[54]
  PIN i_w[55]
    DIRECTION INPUT ;
    USE SIGNAL ;
    PORT
      LAYER M4 ;
        RECT  0 81.792 0.192 81.816 ;
    END
  END i_w[55]
  PIN i_w[56]
    DIRECTION INPUT ;
    USE SIGNAL ;
    PORT
      LAYER M4 ;
        RECT  0 82.176 0.192 82.2 ;
    END
  END i_w[56]
  PIN i_w[57]
    DIRECTION INPUT ;
    USE SIGNAL ;
    PORT
      LAYER M4 ;
        RECT  0 82.56 0.192 82.584 ;
    END
  END i_w[57]
  PIN i_w[58]
    DIRECTION INPUT ;
    USE SIGNAL ;
    PORT
      LAYER M4 ;
        RECT  0 82.944 0.192 82.968 ;
    END
  END i_w[58]
  PIN i_w[59]
    DIRECTION INPUT ;
    USE SIGNAL ;
    PORT
      LAYER M4 ;
        RECT  0 83.328 0.192 83.352 ;
    END
  END i_w[59]
  PIN i_w[5]
    DIRECTION INPUT ;
    USE SIGNAL ;
    PORT
      LAYER M4 ;
        RECT  0 62.592 0.192 62.616 ;
    END
  END i_w[5]
  PIN i_w[60]
    DIRECTION INPUT ;
    USE SIGNAL ;
    PORT
      LAYER M4 ;
        RECT  0 83.712 0.192 83.736 ;
    END
  END i_w[60]
  PIN i_w[61]
    DIRECTION INPUT ;
    USE SIGNAL ;
    PORT
      LAYER M4 ;
        RECT  0 84.096 0.192 84.12 ;
    END
  END i_w[61]
  PIN i_w[62]
    DIRECTION INPUT ;
    USE SIGNAL ;
    PORT
      LAYER M4 ;
        RECT  0 84.48 0.192 84.504 ;
    END
  END i_w[62]
  PIN i_w[63]
    DIRECTION INPUT ;
    USE SIGNAL ;
    PORT
      LAYER M4 ;
        RECT  0 84.864 0.192 84.888 ;
    END
  END i_w[63]
  PIN i_w[64]
    DIRECTION INPUT ;
    USE SIGNAL ;
    PORT
      LAYER M4 ;
        RECT  0 85.248 0.192 85.272 ;
    END
  END i_w[64]
  PIN i_w[65]
    DIRECTION INPUT ;
    USE SIGNAL ;
    PORT
      LAYER M4 ;
        RECT  0 85.632 0.192 85.656 ;
    END
  END i_w[65]
  PIN i_w[66]
    DIRECTION INPUT ;
    USE SIGNAL ;
    PORT
      LAYER M4 ;
        RECT  0 86.016 0.192 86.04 ;
    END
  END i_w[66]
  PIN i_w[67]
    DIRECTION INPUT ;
    USE SIGNAL ;
    PORT
      LAYER M4 ;
        RECT  0 86.4 0.192 86.424 ;
    END
  END i_w[67]
  PIN i_w[68]
    DIRECTION INPUT ;
    USE SIGNAL ;
    PORT
      LAYER M4 ;
        RECT  0 86.784 0.192 86.808 ;
    END
  END i_w[68]
  PIN i_w[69]
    DIRECTION INPUT ;
    USE SIGNAL ;
    PORT
      LAYER M4 ;
        RECT  0 87.168 0.192 87.192 ;
    END
  END i_w[69]
  PIN i_w[6]
    DIRECTION INPUT ;
    USE SIGNAL ;
    PORT
      LAYER M4 ;
        RECT  0 62.976 0.192 63 ;
    END
  END i_w[6]
  PIN i_w[70]
    DIRECTION INPUT ;
    USE SIGNAL ;
    PORT
      LAYER M4 ;
        RECT  0 87.552 0.192 87.576 ;
    END
  END i_w[70]
  PIN i_w[71]
    DIRECTION INPUT ;
    USE SIGNAL ;
    PORT
      LAYER M4 ;
        RECT  0 87.936 0.192 87.96 ;
    END
  END i_w[71]
  PIN i_w[72]
    DIRECTION INPUT ;
    USE SIGNAL ;
    PORT
      LAYER M4 ;
        RECT  0 88.32 0.192 88.344 ;
    END
  END i_w[72]
  PIN i_w[73]
    DIRECTION INPUT ;
    USE SIGNAL ;
    PORT
      LAYER M4 ;
        RECT  0 88.704 0.192 88.728 ;
    END
  END i_w[73]
  PIN i_w[74]
    DIRECTION INPUT ;
    USE SIGNAL ;
    PORT
      LAYER M4 ;
        RECT  0 89.088 0.192 89.112 ;
    END
  END i_w[74]
  PIN i_w[75]
    DIRECTION INPUT ;
    USE SIGNAL ;
    PORT
      LAYER M4 ;
        RECT  0 89.472 0.192 89.496 ;
    END
  END i_w[75]
  PIN i_w[76]
    DIRECTION INPUT ;
    USE SIGNAL ;
    PORT
      LAYER M4 ;
        RECT  0 89.856 0.192 89.88 ;
    END
  END i_w[76]
  PIN i_w[77]
    DIRECTION INPUT ;
    USE SIGNAL ;
    PORT
      LAYER M4 ;
        RECT  0 90.24 0.192 90.264 ;
    END
  END i_w[77]
  PIN i_w[78]
    DIRECTION INPUT ;
    USE SIGNAL ;
    PORT
      LAYER M4 ;
        RECT  0 90.624 0.192 90.648 ;
    END
  END i_w[78]
  PIN i_w[79]
    DIRECTION INPUT ;
    USE SIGNAL ;
    PORT
      LAYER M4 ;
        RECT  0 91.008 0.192 91.032 ;
    END
  END i_w[79]
  PIN i_w[7]
    DIRECTION INPUT ;
    USE SIGNAL ;
    PORT
      LAYER M4 ;
        RECT  0 63.36 0.192 63.384 ;
    END
  END i_w[7]
  PIN i_w[80]
    DIRECTION INPUT ;
    USE SIGNAL ;
    PORT
      LAYER M4 ;
        RECT  0 91.392 0.192 91.416 ;
    END
  END i_w[80]
  PIN i_w[81]
    DIRECTION INPUT ;
    USE SIGNAL ;
    PORT
      LAYER M4 ;
        RECT  0 91.776 0.192 91.8 ;
    END
  END i_w[81]
  PIN i_w[82]
    DIRECTION INPUT ;
    USE SIGNAL ;
    PORT
      LAYER M4 ;
        RECT  0 92.16 0.192 92.184 ;
    END
  END i_w[82]
  PIN i_w[83]
    DIRECTION INPUT ;
    USE SIGNAL ;
    PORT
      LAYER M4 ;
        RECT  0 92.544 0.192 92.568 ;
    END
  END i_w[83]
  PIN i_w[84]
    DIRECTION INPUT ;
    USE SIGNAL ;
    PORT
      LAYER M4 ;
        RECT  0 92.928 0.192 92.952 ;
    END
  END i_w[84]
  PIN i_w[85]
    DIRECTION INPUT ;
    USE SIGNAL ;
    PORT
      LAYER M4 ;
        RECT  0 93.312 0.192 93.336 ;
    END
  END i_w[85]
  PIN i_w[86]
    DIRECTION INPUT ;
    USE SIGNAL ;
    PORT
      LAYER M4 ;
        RECT  0 93.696 0.192 93.72 ;
    END
  END i_w[86]
  PIN i_w[87]
    DIRECTION INPUT ;
    USE SIGNAL ;
    PORT
      LAYER M4 ;
        RECT  0 94.08 0.192 94.104 ;
    END
  END i_w[87]
  PIN i_w[88]
    DIRECTION INPUT ;
    USE SIGNAL ;
    PORT
      LAYER M4 ;
        RECT  0 94.464 0.192 94.488 ;
    END
  END i_w[88]
  PIN i_w[89]
    DIRECTION INPUT ;
    USE SIGNAL ;
    PORT
      LAYER M4 ;
        RECT  0 94.848 0.192 94.872 ;
    END
  END i_w[89]
  PIN i_w[8]
    DIRECTION INPUT ;
    USE SIGNAL ;
    PORT
      LAYER M4 ;
        RECT  0 63.744 0.192 63.768 ;
    END
  END i_w[8]
  PIN i_w[90]
    DIRECTION INPUT ;
    USE SIGNAL ;
    PORT
      LAYER M4 ;
        RECT  0 95.232 0.192 95.256 ;
    END
  END i_w[90]
  PIN i_w[91]
    DIRECTION INPUT ;
    USE SIGNAL ;
    PORT
      LAYER M4 ;
        RECT  0 95.616 0.192 95.64 ;
    END
  END i_w[91]
  PIN i_w[92]
    DIRECTION INPUT ;
    USE SIGNAL ;
    PORT
      LAYER M4 ;
        RECT  0 96 0.192 96.024 ;
    END
  END i_w[92]
  PIN i_w[93]
    DIRECTION INPUT ;
    USE SIGNAL ;
    PORT
      LAYER M4 ;
        RECT  0 96.384 0.192 96.408 ;
    END
  END i_w[93]
  PIN i_w[94]
    DIRECTION INPUT ;
    USE SIGNAL ;
    PORT
      LAYER M4 ;
        RECT  0 96.768 0.192 96.792 ;
    END
  END i_w[94]
  PIN i_w[95]
    DIRECTION INPUT ;
    USE SIGNAL ;
    PORT
      LAYER M4 ;
        RECT  0 97.152 0.192 97.176 ;
    END
  END i_w[95]
  PIN i_w[96]
    DIRECTION INPUT ;
    USE SIGNAL ;
    PORT
      LAYER M4 ;
        RECT  0 97.536 0.192 97.56 ;
    END
  END i_w[96]
  PIN i_w[97]
    DIRECTION INPUT ;
    USE SIGNAL ;
    PORT
      LAYER M4 ;
        RECT  0 97.92 0.192 97.944 ;
    END
  END i_w[97]
  PIN i_w[98]
    DIRECTION INPUT ;
    USE SIGNAL ;
    PORT
      LAYER M4 ;
        RECT  0 98.304 0.192 98.328 ;
    END
  END i_w[98]
  PIN i_w[99]
    DIRECTION INPUT ;
    USE SIGNAL ;
    PORT
      LAYER M4 ;
        RECT  0 98.688 0.192 98.712 ;
    END
  END i_w[99]
  PIN i_w[9]
    DIRECTION INPUT ;
    USE SIGNAL ;
    PORT
      LAYER M4 ;
        RECT  0 64.128 0.192 64.152 ;
    END
  END i_w[9]
  PIN i_x[0]
    DIRECTION INPUT ;
    USE SIGNAL ;
    PORT
      LAYER M4 ;
        RECT  0 60.864 0.192 60.888 ;
    END
  END i_x[0]
  PIN i_x[100]
    DIRECTION INPUT ;
    USE SIGNAL ;
    PORT
      LAYER M4 ;
        RECT  0 99.264 0.192 99.288 ;
    END
  END i_x[100]
  PIN i_x[101]
    DIRECTION INPUT ;
    USE SIGNAL ;
    PORT
      LAYER M4 ;
        RECT  0 99.648 0.192 99.672 ;
    END
  END i_x[101]
  PIN i_x[102]
    DIRECTION INPUT ;
    USE SIGNAL ;
    PORT
      LAYER M4 ;
        RECT  0 100.032 0.192 100.056 ;
    END
  END i_x[102]
  PIN i_x[103]
    DIRECTION INPUT ;
    USE SIGNAL ;
    PORT
      LAYER M4 ;
        RECT  0 100.416 0.192 100.44 ;
    END
  END i_x[103]
  PIN i_x[104]
    DIRECTION INPUT ;
    USE SIGNAL ;
    PORT
      LAYER M4 ;
        RECT  0 100.8 0.192 100.824 ;
    END
  END i_x[104]
  PIN i_x[105]
    DIRECTION INPUT ;
    USE SIGNAL ;
    PORT
      LAYER M4 ;
        RECT  0 101.184 0.192 101.208 ;
    END
  END i_x[105]
  PIN i_x[106]
    DIRECTION INPUT ;
    USE SIGNAL ;
    PORT
      LAYER M4 ;
        RECT  0 101.568 0.192 101.592 ;
    END
  END i_x[106]
  PIN i_x[107]
    DIRECTION INPUT ;
    USE SIGNAL ;
    PORT
      LAYER M4 ;
        RECT  0 101.952 0.192 101.976 ;
    END
  END i_x[107]
  PIN i_x[108]
    DIRECTION INPUT ;
    USE SIGNAL ;
    PORT
      LAYER M4 ;
        RECT  0 102.336 0.192 102.36 ;
    END
  END i_x[108]
  PIN i_x[109]
    DIRECTION INPUT ;
    USE SIGNAL ;
    PORT
      LAYER M4 ;
        RECT  0 102.72 0.192 102.744 ;
    END
  END i_x[109]
  PIN i_x[10]
    DIRECTION INPUT ;
    USE SIGNAL ;
    PORT
      LAYER M4 ;
        RECT  0 64.704 0.192 64.728 ;
    END
  END i_x[10]
  PIN i_x[110]
    DIRECTION INPUT ;
    USE SIGNAL ;
    PORT
      LAYER M4 ;
        RECT  0 103.104 0.192 103.128 ;
    END
  END i_x[110]
  PIN i_x[111]
    DIRECTION INPUT ;
    USE SIGNAL ;
    PORT
      LAYER M4 ;
        RECT  0 103.488 0.192 103.512 ;
    END
  END i_x[111]
  PIN i_x[112]
    DIRECTION INPUT ;
    USE SIGNAL ;
    PORT
      LAYER M4 ;
        RECT  0 103.872 0.192 103.896 ;
    END
  END i_x[112]
  PIN i_x[113]
    DIRECTION INPUT ;
    USE SIGNAL ;
    PORT
      LAYER M4 ;
        RECT  0 104.256 0.192 104.28 ;
    END
  END i_x[113]
  PIN i_x[114]
    DIRECTION INPUT ;
    USE SIGNAL ;
    PORT
      LAYER M4 ;
        RECT  0 104.64 0.192 104.664 ;
    END
  END i_x[114]
  PIN i_x[115]
    DIRECTION INPUT ;
    USE SIGNAL ;
    PORT
      LAYER M4 ;
        RECT  0 105.024 0.192 105.048 ;
    END
  END i_x[115]
  PIN i_x[116]
    DIRECTION INPUT ;
    USE SIGNAL ;
    PORT
      LAYER M4 ;
        RECT  0 105.408 0.192 105.432 ;
    END
  END i_x[116]
  PIN i_x[117]
    DIRECTION INPUT ;
    USE SIGNAL ;
    PORT
      LAYER M4 ;
        RECT  0 105.792 0.192 105.816 ;
    END
  END i_x[117]
  PIN i_x[118]
    DIRECTION INPUT ;
    USE SIGNAL ;
    PORT
      LAYER M4 ;
        RECT  0 106.176 0.192 106.2 ;
    END
  END i_x[118]
  PIN i_x[119]
    DIRECTION INPUT ;
    USE SIGNAL ;
    PORT
      LAYER M4 ;
        RECT  0 106.56 0.192 106.584 ;
    END
  END i_x[119]
  PIN i_x[11]
    DIRECTION INPUT ;
    USE SIGNAL ;
    PORT
      LAYER M4 ;
        RECT  0 65.088 0.192 65.112 ;
    END
  END i_x[11]
  PIN i_x[120]
    DIRECTION INPUT ;
    USE SIGNAL ;
    PORT
      LAYER M4 ;
        RECT  0 106.944 0.192 106.968 ;
    END
  END i_x[120]
  PIN i_x[121]
    DIRECTION INPUT ;
    USE SIGNAL ;
    PORT
      LAYER M4 ;
        RECT  0 107.328 0.192 107.352 ;
    END
  END i_x[121]
  PIN i_x[122]
    DIRECTION INPUT ;
    USE SIGNAL ;
    PORT
      LAYER M4 ;
        RECT  0 107.712 0.192 107.736 ;
    END
  END i_x[122]
  PIN i_x[123]
    DIRECTION INPUT ;
    USE SIGNAL ;
    PORT
      LAYER M4 ;
        RECT  0 108.096 0.192 108.12 ;
    END
  END i_x[123]
  PIN i_x[124]
    DIRECTION INPUT ;
    USE SIGNAL ;
    PORT
      LAYER M4 ;
        RECT  0 108.48 0.192 108.504 ;
    END
  END i_x[124]
  PIN i_x[125]
    DIRECTION INPUT ;
    USE SIGNAL ;
    PORT
      LAYER M4 ;
        RECT  0 108.864 0.192 108.888 ;
    END
  END i_x[125]
  PIN i_x[126]
    DIRECTION INPUT ;
    USE SIGNAL ;
    PORT
      LAYER M4 ;
        RECT  0 109.248 0.192 109.272 ;
    END
  END i_x[126]
  PIN i_x[127]
    DIRECTION INPUT ;
    USE SIGNAL ;
    PORT
      LAYER M4 ;
        RECT  0 109.632 0.192 109.656 ;
    END
  END i_x[127]
  PIN i_x[128]
    DIRECTION INPUT ;
    USE SIGNAL ;
    PORT
      LAYER M4 ;
        RECT  0 110.016 0.192 110.04 ;
    END
  END i_x[128]
  PIN i_x[129]
    DIRECTION INPUT ;
    USE SIGNAL ;
    PORT
      LAYER M4 ;
        RECT  0 110.4 0.192 110.424 ;
    END
  END i_x[129]
  PIN i_x[12]
    DIRECTION INPUT ;
    USE SIGNAL ;
    PORT
      LAYER M4 ;
        RECT  0 65.472 0.192 65.496 ;
    END
  END i_x[12]
  PIN i_x[130]
    DIRECTION INPUT ;
    USE SIGNAL ;
    PORT
      LAYER M4 ;
        RECT  0 110.784 0.192 110.808 ;
    END
  END i_x[130]
  PIN i_x[131]
    DIRECTION INPUT ;
    USE SIGNAL ;
    PORT
      LAYER M4 ;
        RECT  0 111.168 0.192 111.192 ;
    END
  END i_x[131]
  PIN i_x[132]
    DIRECTION INPUT ;
    USE SIGNAL ;
    PORT
      LAYER M4 ;
        RECT  0 111.552 0.192 111.576 ;
    END
  END i_x[132]
  PIN i_x[133]
    DIRECTION INPUT ;
    USE SIGNAL ;
    PORT
      LAYER M4 ;
        RECT  0 111.936 0.192 111.96 ;
    END
  END i_x[133]
  PIN i_x[134]
    DIRECTION INPUT ;
    USE SIGNAL ;
    PORT
      LAYER M4 ;
        RECT  0 112.32 0.192 112.344 ;
    END
  END i_x[134]
  PIN i_x[135]
    DIRECTION INPUT ;
    USE SIGNAL ;
    PORT
      LAYER M4 ;
        RECT  0 112.704 0.192 112.728 ;
    END
  END i_x[135]
  PIN i_x[136]
    DIRECTION INPUT ;
    USE SIGNAL ;
    PORT
      LAYER M4 ;
        RECT  0 113.088 0.192 113.112 ;
    END
  END i_x[136]
  PIN i_x[137]
    DIRECTION INPUT ;
    USE SIGNAL ;
    PORT
      LAYER M4 ;
        RECT  0 113.472 0.192 113.496 ;
    END
  END i_x[137]
  PIN i_x[138]
    DIRECTION INPUT ;
    USE SIGNAL ;
    PORT
      LAYER M4 ;
        RECT  0 113.856 0.192 113.88 ;
    END
  END i_x[138]
  PIN i_x[139]
    DIRECTION INPUT ;
    USE SIGNAL ;
    PORT
      LAYER M4 ;
        RECT  0 114.24 0.192 114.264 ;
    END
  END i_x[139]
  PIN i_x[13]
    DIRECTION INPUT ;
    USE SIGNAL ;
    PORT
      LAYER M4 ;
        RECT  0 65.856 0.192 65.88 ;
    END
  END i_x[13]
  PIN i_x[140]
    DIRECTION INPUT ;
    USE SIGNAL ;
    PORT
      LAYER M4 ;
        RECT  0 114.624 0.192 114.648 ;
    END
  END i_x[140]
  PIN i_x[141]
    DIRECTION INPUT ;
    USE SIGNAL ;
    PORT
      LAYER M4 ;
        RECT  0 115.008 0.192 115.032 ;
    END
  END i_x[141]
  PIN i_x[142]
    DIRECTION INPUT ;
    USE SIGNAL ;
    PORT
      LAYER M4 ;
        RECT  0 115.392 0.192 115.416 ;
    END
  END i_x[142]
  PIN i_x[143]
    DIRECTION INPUT ;
    USE SIGNAL ;
    PORT
      LAYER M4 ;
        RECT  0 115.776 0.192 115.8 ;
    END
  END i_x[143]
  PIN i_x[144]
    DIRECTION INPUT ;
    USE SIGNAL ;
    PORT
      LAYER M4 ;
        RECT  0 116.16 0.192 116.184 ;
    END
  END i_x[144]
  PIN i_x[145]
    DIRECTION INPUT ;
    USE SIGNAL ;
    PORT
      LAYER M4 ;
        RECT  0 116.544 0.192 116.568 ;
    END
  END i_x[145]
  PIN i_x[146]
    DIRECTION INPUT ;
    USE SIGNAL ;
    PORT
      LAYER M4 ;
        RECT  0 116.928 0.192 116.952 ;
    END
  END i_x[146]
  PIN i_x[147]
    DIRECTION INPUT ;
    USE SIGNAL ;
    PORT
      LAYER M4 ;
        RECT  0 117.312 0.192 117.336 ;
    END
  END i_x[147]
  PIN i_x[148]
    DIRECTION INPUT ;
    USE SIGNAL ;
    PORT
      LAYER M4 ;
        RECT  0 117.696 0.192 117.72 ;
    END
  END i_x[148]
  PIN i_x[149]
    DIRECTION INPUT ;
    USE SIGNAL ;
    PORT
      LAYER M4 ;
        RECT  0 118.08 0.192 118.104 ;
    END
  END i_x[149]
  PIN i_x[14]
    DIRECTION INPUT ;
    USE SIGNAL ;
    PORT
      LAYER M4 ;
        RECT  0 66.24 0.192 66.264 ;
    END
  END i_x[14]
  PIN i_x[150]
    DIRECTION INPUT ;
    USE SIGNAL ;
    PORT
      LAYER M4 ;
        RECT  0 118.464 0.192 118.488 ;
    END
  END i_x[150]
  PIN i_x[151]
    DIRECTION INPUT ;
    USE SIGNAL ;
    PORT
      LAYER M4 ;
        RECT  0 118.848 0.192 118.872 ;
    END
  END i_x[151]
  PIN i_x[152]
    DIRECTION INPUT ;
    USE SIGNAL ;
    PORT
      LAYER M4 ;
        RECT  0 119.232 0.192 119.256 ;
    END
  END i_x[152]
  PIN i_x[153]
    DIRECTION INPUT ;
    USE SIGNAL ;
    PORT
      LAYER M4 ;
        RECT  0 119.616 0.192 119.64 ;
    END
  END i_x[153]
  PIN i_x[154]
    DIRECTION INPUT ;
    USE SIGNAL ;
    PORT
      LAYER M4 ;
        RECT  0 120 0.192 120.024 ;
    END
  END i_x[154]
  PIN i_x[155]
    DIRECTION INPUT ;
    USE SIGNAL ;
    PORT
      LAYER M4 ;
        RECT  0 120.384 0.192 120.408 ;
    END
  END i_x[155]
  PIN i_x[156]
    DIRECTION INPUT ;
    USE SIGNAL ;
    PORT
      LAYER M4 ;
        RECT  0 120.768 0.192 120.792 ;
    END
  END i_x[156]
  PIN i_x[157]
    DIRECTION INPUT ;
    USE SIGNAL ;
    PORT
      LAYER M4 ;
        RECT  0 121.152 0.192 121.176 ;
    END
  END i_x[157]
  PIN i_x[158]
    DIRECTION INPUT ;
    USE SIGNAL ;
    PORT
      LAYER M4 ;
        RECT  0 121.536 0.192 121.56 ;
    END
  END i_x[158]
  PIN i_x[159]
    DIRECTION INPUT ;
    USE SIGNAL ;
    PORT
      LAYER M4 ;
        RECT  0 121.92 0.192 121.944 ;
    END
  END i_x[159]
  PIN i_x[15]
    DIRECTION INPUT ;
    USE SIGNAL ;
    PORT
      LAYER M4 ;
        RECT  0 66.624 0.192 66.648 ;
    END
  END i_x[15]
  PIN i_x[160]
    DIRECTION INPUT ;
    USE SIGNAL ;
    PORT
      LAYER M4 ;
        RECT  0 122.304 0.192 122.328 ;
    END
  END i_x[160]
  PIN i_x[161]
    DIRECTION INPUT ;
    USE SIGNAL ;
    PORT
      LAYER M4 ;
        RECT  0 122.688 0.192 122.712 ;
    END
  END i_x[161]
  PIN i_x[162]
    DIRECTION INPUT ;
    USE SIGNAL ;
    PORT
      LAYER M4 ;
        RECT  0 123.072 0.192 123.096 ;
    END
  END i_x[162]
  PIN i_x[163]
    DIRECTION INPUT ;
    USE SIGNAL ;
    PORT
      LAYER M4 ;
        RECT  0 123.456 0.192 123.48 ;
    END
  END i_x[163]
  PIN i_x[164]
    DIRECTION INPUT ;
    USE SIGNAL ;
    PORT
      LAYER M4 ;
        RECT  0 123.84 0.192 123.864 ;
    END
  END i_x[164]
  PIN i_x[165]
    DIRECTION INPUT ;
    USE SIGNAL ;
    PORT
      LAYER M4 ;
        RECT  0 124.224 0.192 124.248 ;
    END
  END i_x[165]
  PIN i_x[166]
    DIRECTION INPUT ;
    USE SIGNAL ;
    PORT
      LAYER M4 ;
        RECT  0 124.608 0.192 124.632 ;
    END
  END i_x[166]
  PIN i_x[167]
    DIRECTION INPUT ;
    USE SIGNAL ;
    PORT
      LAYER M4 ;
        RECT  0 124.992 0.192 125.016 ;
    END
  END i_x[167]
  PIN i_x[168]
    DIRECTION INPUT ;
    USE SIGNAL ;
    PORT
      LAYER M4 ;
        RECT  0 125.376 0.192 125.4 ;
    END
  END i_x[168]
  PIN i_x[169]
    DIRECTION INPUT ;
    USE SIGNAL ;
    PORT
      LAYER M4 ;
        RECT  0 125.76 0.192 125.784 ;
    END
  END i_x[169]
  PIN i_x[16]
    DIRECTION INPUT ;
    USE SIGNAL ;
    PORT
      LAYER M4 ;
        RECT  0 67.008 0.192 67.032 ;
    END
  END i_x[16]
  PIN i_x[170]
    DIRECTION INPUT ;
    USE SIGNAL ;
    PORT
      LAYER M4 ;
        RECT  0 126.144 0.192 126.168 ;
    END
  END i_x[170]
  PIN i_x[171]
    DIRECTION INPUT ;
    USE SIGNAL ;
    PORT
      LAYER M4 ;
        RECT  0 126.528 0.192 126.552 ;
    END
  END i_x[171]
  PIN i_x[172]
    DIRECTION INPUT ;
    USE SIGNAL ;
    PORT
      LAYER M4 ;
        RECT  0 126.912 0.192 126.936 ;
    END
  END i_x[172]
  PIN i_x[173]
    DIRECTION INPUT ;
    USE SIGNAL ;
    PORT
      LAYER M4 ;
        RECT  0 127.296 0.192 127.32 ;
    END
  END i_x[173]
  PIN i_x[174]
    DIRECTION INPUT ;
    USE SIGNAL ;
    PORT
      LAYER M4 ;
        RECT  0 127.68 0.192 127.704 ;
    END
  END i_x[174]
  PIN i_x[175]
    DIRECTION INPUT ;
    USE SIGNAL ;
    PORT
      LAYER M4 ;
        RECT  0 128.064 0.192 128.088 ;
    END
  END i_x[175]
  PIN i_x[176]
    DIRECTION INPUT ;
    USE SIGNAL ;
    PORT
      LAYER M4 ;
        RECT  0 128.448 0.192 128.472 ;
    END
  END i_x[176]
  PIN i_x[177]
    DIRECTION INPUT ;
    USE SIGNAL ;
    PORT
      LAYER M4 ;
        RECT  0 128.832 0.192 128.856 ;
    END
  END i_x[177]
  PIN i_x[178]
    DIRECTION INPUT ;
    USE SIGNAL ;
    PORT
      LAYER M4 ;
        RECT  0 129.216 0.192 129.24 ;
    END
  END i_x[178]
  PIN i_x[179]
    DIRECTION INPUT ;
    USE SIGNAL ;
    PORT
      LAYER M4 ;
        RECT  0 129.6 0.192 129.624 ;
    END
  END i_x[179]
  PIN i_x[17]
    DIRECTION INPUT ;
    USE SIGNAL ;
    PORT
      LAYER M4 ;
        RECT  0 67.392 0.192 67.416 ;
    END
  END i_x[17]
  PIN i_x[180]
    DIRECTION INPUT ;
    USE SIGNAL ;
    PORT
      LAYER M4 ;
        RECT  0 129.984 0.192 130.008 ;
    END
  END i_x[180]
  PIN i_x[181]
    DIRECTION INPUT ;
    USE SIGNAL ;
    PORT
      LAYER M4 ;
        RECT  0 130.368 0.192 130.392 ;
    END
  END i_x[181]
  PIN i_x[182]
    DIRECTION INPUT ;
    USE SIGNAL ;
    PORT
      LAYER M4 ;
        RECT  0 130.752 0.192 130.776 ;
    END
  END i_x[182]
  PIN i_x[183]
    DIRECTION INPUT ;
    USE SIGNAL ;
    PORT
      LAYER M4 ;
        RECT  0 131.136 0.192 131.16 ;
    END
  END i_x[183]
  PIN i_x[184]
    DIRECTION INPUT ;
    USE SIGNAL ;
    PORT
      LAYER M4 ;
        RECT  0 131.52 0.192 131.544 ;
    END
  END i_x[184]
  PIN i_x[185]
    DIRECTION INPUT ;
    USE SIGNAL ;
    PORT
      LAYER M4 ;
        RECT  0 131.904 0.192 131.928 ;
    END
  END i_x[185]
  PIN i_x[186]
    DIRECTION INPUT ;
    USE SIGNAL ;
    PORT
      LAYER M4 ;
        RECT  0 132.288 0.192 132.312 ;
    END
  END i_x[186]
  PIN i_x[187]
    DIRECTION INPUT ;
    USE SIGNAL ;
    PORT
      LAYER M4 ;
        RECT  0 132.672 0.192 132.696 ;
    END
  END i_x[187]
  PIN i_x[188]
    DIRECTION INPUT ;
    USE SIGNAL ;
    PORT
      LAYER M4 ;
        RECT  0 133.056 0.192 133.08 ;
    END
  END i_x[188]
  PIN i_x[189]
    DIRECTION INPUT ;
    USE SIGNAL ;
    PORT
      LAYER M4 ;
        RECT  0 133.44 0.192 133.464 ;
    END
  END i_x[189]
  PIN i_x[18]
    DIRECTION INPUT ;
    USE SIGNAL ;
    PORT
      LAYER M4 ;
        RECT  0 67.776 0.192 67.8 ;
    END
  END i_x[18]
  PIN i_x[190]
    DIRECTION INPUT ;
    USE SIGNAL ;
    PORT
      LAYER M4 ;
        RECT  0 133.824 0.192 133.848 ;
    END
  END i_x[190]
  PIN i_x[191]
    DIRECTION INPUT ;
    USE SIGNAL ;
    PORT
      LAYER M4 ;
        RECT  0 134.208 0.192 134.232 ;
    END
  END i_x[191]
  PIN i_x[192]
    DIRECTION INPUT ;
    USE SIGNAL ;
    PORT
      LAYER M4 ;
        RECT  0 134.592 0.192 134.616 ;
    END
  END i_x[192]
  PIN i_x[193]
    DIRECTION INPUT ;
    USE SIGNAL ;
    PORT
      LAYER M4 ;
        RECT  0 134.976 0.192 135 ;
    END
  END i_x[193]
  PIN i_x[194]
    DIRECTION INPUT ;
    USE SIGNAL ;
    PORT
      LAYER M4 ;
        RECT  0 135.36 0.192 135.384 ;
    END
  END i_x[194]
  PIN i_x[195]
    DIRECTION INPUT ;
    USE SIGNAL ;
    PORT
      LAYER M4 ;
        RECT  0 135.744 0.192 135.768 ;
    END
  END i_x[195]
  PIN i_x[196]
    DIRECTION INPUT ;
    USE SIGNAL ;
    PORT
      LAYER M4 ;
        RECT  0 136.128 0.192 136.152 ;
    END
  END i_x[196]
  PIN i_x[197]
    DIRECTION INPUT ;
    USE SIGNAL ;
    PORT
      LAYER M4 ;
        RECT  0 136.512 0.192 136.536 ;
    END
  END i_x[197]
  PIN i_x[198]
    DIRECTION INPUT ;
    USE SIGNAL ;
    PORT
      LAYER M4 ;
        RECT  0 136.896 0.192 136.92 ;
    END
  END i_x[198]
  PIN i_x[199]
    DIRECTION INPUT ;
    USE SIGNAL ;
    PORT
      LAYER M4 ;
        RECT  0 137.28 0.192 137.304 ;
    END
  END i_x[199]
  PIN i_x[19]
    DIRECTION INPUT ;
    USE SIGNAL ;
    PORT
      LAYER M4 ;
        RECT  0 68.16 0.192 68.184 ;
    END
  END i_x[19]
  PIN i_x[1]
    DIRECTION INPUT ;
    USE SIGNAL ;
    PORT
      LAYER M4 ;
        RECT  0 61.248 0.192 61.272 ;
    END
  END i_x[1]
  PIN i_x[200]
    DIRECTION INPUT ;
    USE SIGNAL ;
    PORT
      LAYER M4 ;
        RECT  0 137.664 0.192 137.688 ;
    END
  END i_x[200]
  PIN i_x[201]
    DIRECTION INPUT ;
    USE SIGNAL ;
    PORT
      LAYER M4 ;
        RECT  0 138.048 0.192 138.072 ;
    END
  END i_x[201]
  PIN i_x[202]
    DIRECTION INPUT ;
    USE SIGNAL ;
    PORT
      LAYER M4 ;
        RECT  0 138.432 0.192 138.456 ;
    END
  END i_x[202]
  PIN i_x[203]
    DIRECTION INPUT ;
    USE SIGNAL ;
    PORT
      LAYER M4 ;
        RECT  0 138.816 0.192 138.84 ;
    END
  END i_x[203]
  PIN i_x[204]
    DIRECTION INPUT ;
    USE SIGNAL ;
    PORT
      LAYER M4 ;
        RECT  0 139.2 0.192 139.224 ;
    END
  END i_x[204]
  PIN i_x[205]
    DIRECTION INPUT ;
    USE SIGNAL ;
    PORT
      LAYER M4 ;
        RECT  0 139.584 0.192 139.608 ;
    END
  END i_x[205]
  PIN i_x[206]
    DIRECTION INPUT ;
    USE SIGNAL ;
    PORT
      LAYER M4 ;
        RECT  0 139.968 0.192 139.992 ;
    END
  END i_x[206]
  PIN i_x[207]
    DIRECTION INPUT ;
    USE SIGNAL ;
    PORT
      LAYER M4 ;
        RECT  0 140.352 0.192 140.376 ;
    END
  END i_x[207]
  PIN i_x[208]
    DIRECTION INPUT ;
    USE SIGNAL ;
    PORT
      LAYER M4 ;
        RECT  0 140.736 0.192 140.76 ;
    END
  END i_x[208]
  PIN i_x[209]
    DIRECTION INPUT ;
    USE SIGNAL ;
    PORT
      LAYER M4 ;
        RECT  0 141.12 0.192 141.144 ;
    END
  END i_x[209]
  PIN i_x[20]
    DIRECTION INPUT ;
    USE SIGNAL ;
    PORT
      LAYER M4 ;
        RECT  0 68.544 0.192 68.568 ;
    END
  END i_x[20]
  PIN i_x[210]
    DIRECTION INPUT ;
    USE SIGNAL ;
    PORT
      LAYER M4 ;
        RECT  0 141.504 0.192 141.528 ;
    END
  END i_x[210]
  PIN i_x[211]
    DIRECTION INPUT ;
    USE SIGNAL ;
    PORT
      LAYER M4 ;
        RECT  0 141.888 0.192 141.912 ;
    END
  END i_x[211]
  PIN i_x[212]
    DIRECTION INPUT ;
    USE SIGNAL ;
    PORT
      LAYER M4 ;
        RECT  0 142.272 0.192 142.296 ;
    END
  END i_x[212]
  PIN i_x[213]
    DIRECTION INPUT ;
    USE SIGNAL ;
    PORT
      LAYER M4 ;
        RECT  0 142.656 0.192 142.68 ;
    END
  END i_x[213]
  PIN i_x[214]
    DIRECTION INPUT ;
    USE SIGNAL ;
    PORT
      LAYER M4 ;
        RECT  0 143.04 0.192 143.064 ;
    END
  END i_x[214]
  PIN i_x[215]
    DIRECTION INPUT ;
    USE SIGNAL ;
    PORT
      LAYER M4 ;
        RECT  0 143.424 0.192 143.448 ;
    END
  END i_x[215]
  PIN i_x[216]
    DIRECTION INPUT ;
    USE SIGNAL ;
    PORT
      LAYER M4 ;
        RECT  0 143.808 0.192 143.832 ;
    END
  END i_x[216]
  PIN i_x[217]
    DIRECTION INPUT ;
    USE SIGNAL ;
    PORT
      LAYER M4 ;
        RECT  0 144.192 0.192 144.216 ;
    END
  END i_x[217]
  PIN i_x[218]
    DIRECTION INPUT ;
    USE SIGNAL ;
    PORT
      LAYER M4 ;
        RECT  0 144.576 0.192 144.6 ;
    END
  END i_x[218]
  PIN i_x[219]
    DIRECTION INPUT ;
    USE SIGNAL ;
    PORT
      LAYER M4 ;
        RECT  0 144.96 0.192 144.984 ;
    END
  END i_x[219]
  PIN i_x[21]
    DIRECTION INPUT ;
    USE SIGNAL ;
    PORT
      LAYER M4 ;
        RECT  0 68.928 0.192 68.952 ;
    END
  END i_x[21]
  PIN i_x[220]
    DIRECTION INPUT ;
    USE SIGNAL ;
    PORT
      LAYER M4 ;
        RECT  0 145.344 0.192 145.368 ;
    END
  END i_x[220]
  PIN i_x[221]
    DIRECTION INPUT ;
    USE SIGNAL ;
    PORT
      LAYER M4 ;
        RECT  0 145.728 0.192 145.752 ;
    END
  END i_x[221]
  PIN i_x[222]
    DIRECTION INPUT ;
    USE SIGNAL ;
    PORT
      LAYER M4 ;
        RECT  0 146.112 0.192 146.136 ;
    END
  END i_x[222]
  PIN i_x[223]
    DIRECTION INPUT ;
    USE SIGNAL ;
    PORT
      LAYER M4 ;
        RECT  0 146.496 0.192 146.52 ;
    END
  END i_x[223]
  PIN i_x[224]
    DIRECTION INPUT ;
    USE SIGNAL ;
    PORT
      LAYER M4 ;
        RECT  0 146.88 0.192 146.904 ;
    END
  END i_x[224]
  PIN i_x[225]
    DIRECTION INPUT ;
    USE SIGNAL ;
    PORT
      LAYER M4 ;
        RECT  0 147.264 0.192 147.288 ;
    END
  END i_x[225]
  PIN i_x[226]
    DIRECTION INPUT ;
    USE SIGNAL ;
    PORT
      LAYER M4 ;
        RECT  0 147.648 0.192 147.672 ;
    END
  END i_x[226]
  PIN i_x[227]
    DIRECTION INPUT ;
    USE SIGNAL ;
    PORT
      LAYER M4 ;
        RECT  0 148.032 0.192 148.056 ;
    END
  END i_x[227]
  PIN i_x[228]
    DIRECTION INPUT ;
    USE SIGNAL ;
    PORT
      LAYER M4 ;
        RECT  0 148.416 0.192 148.44 ;
    END
  END i_x[228]
  PIN i_x[229]
    DIRECTION INPUT ;
    USE SIGNAL ;
    PORT
      LAYER M4 ;
        RECT  0 148.8 0.192 148.824 ;
    END
  END i_x[229]
  PIN i_x[22]
    DIRECTION INPUT ;
    USE SIGNAL ;
    PORT
      LAYER M4 ;
        RECT  0 69.312 0.192 69.336 ;
    END
  END i_x[22]
  PIN i_x[230]
    DIRECTION INPUT ;
    USE SIGNAL ;
    PORT
      LAYER M4 ;
        RECT  0 149.184 0.192 149.208 ;
    END
  END i_x[230]
  PIN i_x[231]
    DIRECTION INPUT ;
    USE SIGNAL ;
    PORT
      LAYER M4 ;
        RECT  0 149.568 0.192 149.592 ;
    END
  END i_x[231]
  PIN i_x[232]
    DIRECTION INPUT ;
    USE SIGNAL ;
    PORT
      LAYER M4 ;
        RECT  0 149.952 0.192 149.976 ;
    END
  END i_x[232]
  PIN i_x[233]
    DIRECTION INPUT ;
    USE SIGNAL ;
    PORT
      LAYER M4 ;
        RECT  0 150.336 0.192 150.36 ;
    END
  END i_x[233]
  PIN i_x[234]
    DIRECTION INPUT ;
    USE SIGNAL ;
    PORT
      LAYER M4 ;
        RECT  0 150.72 0.192 150.744 ;
    END
  END i_x[234]
  PIN i_x[235]
    DIRECTION INPUT ;
    USE SIGNAL ;
    PORT
      LAYER M4 ;
        RECT  0 151.104 0.192 151.128 ;
    END
  END i_x[235]
  PIN i_x[236]
    DIRECTION INPUT ;
    USE SIGNAL ;
    PORT
      LAYER M4 ;
        RECT  0 151.488 0.192 151.512 ;
    END
  END i_x[236]
  PIN i_x[237]
    DIRECTION INPUT ;
    USE SIGNAL ;
    PORT
      LAYER M4 ;
        RECT  0 151.872 0.192 151.896 ;
    END
  END i_x[237]
  PIN i_x[238]
    DIRECTION INPUT ;
    USE SIGNAL ;
    PORT
      LAYER M4 ;
        RECT  0 152.256 0.192 152.28 ;
    END
  END i_x[238]
  PIN i_x[239]
    DIRECTION INPUT ;
    USE SIGNAL ;
    PORT
      LAYER M4 ;
        RECT  0 152.64 0.192 152.664 ;
    END
  END i_x[239]
  PIN i_x[23]
    DIRECTION INPUT ;
    USE SIGNAL ;
    PORT
      LAYER M4 ;
        RECT  0 69.696 0.192 69.72 ;
    END
  END i_x[23]
  PIN i_x[240]
    DIRECTION INPUT ;
    USE SIGNAL ;
    PORT
      LAYER M4 ;
        RECT  0 153.024 0.192 153.048 ;
    END
  END i_x[240]
  PIN i_x[241]
    DIRECTION INPUT ;
    USE SIGNAL ;
    PORT
      LAYER M4 ;
        RECT  0 153.408 0.192 153.432 ;
    END
  END i_x[241]
  PIN i_x[242]
    DIRECTION INPUT ;
    USE SIGNAL ;
    PORT
      LAYER M4 ;
        RECT  0 153.792 0.192 153.816 ;
    END
  END i_x[242]
  PIN i_x[243]
    DIRECTION INPUT ;
    USE SIGNAL ;
    PORT
      LAYER M4 ;
        RECT  0 154.176 0.192 154.2 ;
    END
  END i_x[243]
  PIN i_x[244]
    DIRECTION INPUT ;
    USE SIGNAL ;
    PORT
      LAYER M4 ;
        RECT  0 154.56 0.192 154.584 ;
    END
  END i_x[244]
  PIN i_x[245]
    DIRECTION INPUT ;
    USE SIGNAL ;
    PORT
      LAYER M4 ;
        RECT  0 154.944 0.192 154.968 ;
    END
  END i_x[245]
  PIN i_x[246]
    DIRECTION INPUT ;
    USE SIGNAL ;
    PORT
      LAYER M4 ;
        RECT  0 155.328 0.192 155.352 ;
    END
  END i_x[246]
  PIN i_x[247]
    DIRECTION INPUT ;
    USE SIGNAL ;
    PORT
      LAYER M4 ;
        RECT  0 155.712 0.192 155.736 ;
    END
  END i_x[247]
  PIN i_x[248]
    DIRECTION INPUT ;
    USE SIGNAL ;
    PORT
      LAYER M4 ;
        RECT  0 156.096 0.192 156.12 ;
    END
  END i_x[248]
  PIN i_x[249]
    DIRECTION INPUT ;
    USE SIGNAL ;
    PORT
      LAYER M4 ;
        RECT  0 156.48 0.192 156.504 ;
    END
  END i_x[249]
  PIN i_x[24]
    DIRECTION INPUT ;
    USE SIGNAL ;
    PORT
      LAYER M4 ;
        RECT  0 70.08 0.192 70.104 ;
    END
  END i_x[24]
  PIN i_x[250]
    DIRECTION INPUT ;
    USE SIGNAL ;
    PORT
      LAYER M4 ;
        RECT  0 156.864 0.192 156.888 ;
    END
  END i_x[250]
  PIN i_x[251]
    DIRECTION INPUT ;
    USE SIGNAL ;
    PORT
      LAYER M4 ;
        RECT  0 157.248 0.192 157.272 ;
    END
  END i_x[251]
  PIN i_x[252]
    DIRECTION INPUT ;
    USE SIGNAL ;
    PORT
      LAYER M4 ;
        RECT  0 157.632 0.192 157.656 ;
    END
  END i_x[252]
  PIN i_x[253]
    DIRECTION INPUT ;
    USE SIGNAL ;
    PORT
      LAYER M4 ;
        RECT  0 158.016 0.192 158.04 ;
    END
  END i_x[253]
  PIN i_x[254]
    DIRECTION INPUT ;
    USE SIGNAL ;
    PORT
      LAYER M4 ;
        RECT  0 158.4 0.192 158.424 ;
    END
  END i_x[254]
  PIN i_x[255]
    DIRECTION INPUT ;
    USE SIGNAL ;
    PORT
      LAYER M4 ;
        RECT  0 158.784 0.192 158.808 ;
    END
  END i_x[255]
  PIN i_x[25]
    DIRECTION INPUT ;
    USE SIGNAL ;
    PORT
      LAYER M4 ;
        RECT  0 70.464 0.192 70.488 ;
    END
  END i_x[25]
  PIN i_x[26]
    DIRECTION INPUT ;
    USE SIGNAL ;
    PORT
      LAYER M4 ;
        RECT  0 70.848 0.192 70.872 ;
    END
  END i_x[26]
  PIN i_x[27]
    DIRECTION INPUT ;
    USE SIGNAL ;
    PORT
      LAYER M4 ;
        RECT  0 71.232 0.192 71.256 ;
    END
  END i_x[27]
  PIN i_x[28]
    DIRECTION INPUT ;
    USE SIGNAL ;
    PORT
      LAYER M4 ;
        RECT  0 71.616 0.192 71.64 ;
    END
  END i_x[28]
  PIN i_x[29]
    DIRECTION INPUT ;
    USE SIGNAL ;
    PORT
      LAYER M4 ;
        RECT  0 72 0.192 72.024 ;
    END
  END i_x[29]
  PIN i_x[2]
    DIRECTION INPUT ;
    USE SIGNAL ;
    PORT
      LAYER M4 ;
        RECT  0 61.632 0.192 61.656 ;
    END
  END i_x[2]
  PIN i_x[30]
    DIRECTION INPUT ;
    USE SIGNAL ;
    PORT
      LAYER M4 ;
        RECT  0 72.384 0.192 72.408 ;
    END
  END i_x[30]
  PIN i_x[31]
    DIRECTION INPUT ;
    USE SIGNAL ;
    PORT
      LAYER M4 ;
        RECT  0 72.768 0.192 72.792 ;
    END
  END i_x[31]
  PIN i_x[32]
    DIRECTION INPUT ;
    USE SIGNAL ;
    PORT
      LAYER M4 ;
        RECT  0 73.152 0.192 73.176 ;
    END
  END i_x[32]
  PIN i_x[33]
    DIRECTION INPUT ;
    USE SIGNAL ;
    PORT
      LAYER M4 ;
        RECT  0 73.536 0.192 73.56 ;
    END
  END i_x[33]
  PIN i_x[34]
    DIRECTION INPUT ;
    USE SIGNAL ;
    PORT
      LAYER M4 ;
        RECT  0 73.92 0.192 73.944 ;
    END
  END i_x[34]
  PIN i_x[35]
    DIRECTION INPUT ;
    USE SIGNAL ;
    PORT
      LAYER M4 ;
        RECT  0 74.304 0.192 74.328 ;
    END
  END i_x[35]
  PIN i_x[36]
    DIRECTION INPUT ;
    USE SIGNAL ;
    PORT
      LAYER M4 ;
        RECT  0 74.688 0.192 74.712 ;
    END
  END i_x[36]
  PIN i_x[37]
    DIRECTION INPUT ;
    USE SIGNAL ;
    PORT
      LAYER M4 ;
        RECT  0 75.072 0.192 75.096 ;
    END
  END i_x[37]
  PIN i_x[38]
    DIRECTION INPUT ;
    USE SIGNAL ;
    PORT
      LAYER M4 ;
        RECT  0 75.456 0.192 75.48 ;
    END
  END i_x[38]
  PIN i_x[39]
    DIRECTION INPUT ;
    USE SIGNAL ;
    PORT
      LAYER M4 ;
        RECT  0 75.84 0.192 75.864 ;
    END
  END i_x[39]
  PIN i_x[3]
    DIRECTION INPUT ;
    USE SIGNAL ;
    PORT
      LAYER M4 ;
        RECT  0 62.016 0.192 62.04 ;
    END
  END i_x[3]
  PIN i_x[40]
    DIRECTION INPUT ;
    USE SIGNAL ;
    PORT
      LAYER M4 ;
        RECT  0 76.224 0.192 76.248 ;
    END
  END i_x[40]
  PIN i_x[41]
    DIRECTION INPUT ;
    USE SIGNAL ;
    PORT
      LAYER M4 ;
        RECT  0 76.608 0.192 76.632 ;
    END
  END i_x[41]
  PIN i_x[42]
    DIRECTION INPUT ;
    USE SIGNAL ;
    PORT
      LAYER M4 ;
        RECT  0 76.992 0.192 77.016 ;
    END
  END i_x[42]
  PIN i_x[43]
    DIRECTION INPUT ;
    USE SIGNAL ;
    PORT
      LAYER M4 ;
        RECT  0 77.376 0.192 77.4 ;
    END
  END i_x[43]
  PIN i_x[44]
    DIRECTION INPUT ;
    USE SIGNAL ;
    PORT
      LAYER M4 ;
        RECT  0 77.76 0.192 77.784 ;
    END
  END i_x[44]
  PIN i_x[45]
    DIRECTION INPUT ;
    USE SIGNAL ;
    PORT
      LAYER M4 ;
        RECT  0 78.144 0.192 78.168 ;
    END
  END i_x[45]
  PIN i_x[46]
    DIRECTION INPUT ;
    USE SIGNAL ;
    PORT
      LAYER M4 ;
        RECT  0 78.528 0.192 78.552 ;
    END
  END i_x[46]
  PIN i_x[47]
    DIRECTION INPUT ;
    USE SIGNAL ;
    PORT
      LAYER M4 ;
        RECT  0 78.912 0.192 78.936 ;
    END
  END i_x[47]
  PIN i_x[48]
    DIRECTION INPUT ;
    USE SIGNAL ;
    PORT
      LAYER M4 ;
        RECT  0 79.296 0.192 79.32 ;
    END
  END i_x[48]
  PIN i_x[49]
    DIRECTION INPUT ;
    USE SIGNAL ;
    PORT
      LAYER M4 ;
        RECT  0 79.68 0.192 79.704 ;
    END
  END i_x[49]
  PIN i_x[4]
    DIRECTION INPUT ;
    USE SIGNAL ;
    PORT
      LAYER M4 ;
        RECT  0 62.4 0.192 62.424 ;
    END
  END i_x[4]
  PIN i_x[50]
    DIRECTION INPUT ;
    USE SIGNAL ;
    PORT
      LAYER M4 ;
        RECT  0 80.064 0.192 80.088 ;
    END
  END i_x[50]
  PIN i_x[51]
    DIRECTION INPUT ;
    USE SIGNAL ;
    PORT
      LAYER M4 ;
        RECT  0 80.448 0.192 80.472 ;
    END
  END i_x[51]
  PIN i_x[52]
    DIRECTION INPUT ;
    USE SIGNAL ;
    PORT
      LAYER M4 ;
        RECT  0 80.832 0.192 80.856 ;
    END
  END i_x[52]
  PIN i_x[53]
    DIRECTION INPUT ;
    USE SIGNAL ;
    PORT
      LAYER M4 ;
        RECT  0 81.216 0.192 81.24 ;
    END
  END i_x[53]
  PIN i_x[54]
    DIRECTION INPUT ;
    USE SIGNAL ;
    PORT
      LAYER M4 ;
        RECT  0 81.6 0.192 81.624 ;
    END
  END i_x[54]
  PIN i_x[55]
    DIRECTION INPUT ;
    USE SIGNAL ;
    PORT
      LAYER M4 ;
        RECT  0 81.984 0.192 82.008 ;
    END
  END i_x[55]
  PIN i_x[56]
    DIRECTION INPUT ;
    USE SIGNAL ;
    PORT
      LAYER M4 ;
        RECT  0 82.368 0.192 82.392 ;
    END
  END i_x[56]
  PIN i_x[57]
    DIRECTION INPUT ;
    USE SIGNAL ;
    PORT
      LAYER M4 ;
        RECT  0 82.752 0.192 82.776 ;
    END
  END i_x[57]
  PIN i_x[58]
    DIRECTION INPUT ;
    USE SIGNAL ;
    PORT
      LAYER M4 ;
        RECT  0 83.136 0.192 83.16 ;
    END
  END i_x[58]
  PIN i_x[59]
    DIRECTION INPUT ;
    USE SIGNAL ;
    PORT
      LAYER M4 ;
        RECT  0 83.52 0.192 83.544 ;
    END
  END i_x[59]
  PIN i_x[5]
    DIRECTION INPUT ;
    USE SIGNAL ;
    PORT
      LAYER M4 ;
        RECT  0 62.784 0.192 62.808 ;
    END
  END i_x[5]
  PIN i_x[60]
    DIRECTION INPUT ;
    USE SIGNAL ;
    PORT
      LAYER M4 ;
        RECT  0 83.904 0.192 83.928 ;
    END
  END i_x[60]
  PIN i_x[61]
    DIRECTION INPUT ;
    USE SIGNAL ;
    PORT
      LAYER M4 ;
        RECT  0 84.288 0.192 84.312 ;
    END
  END i_x[61]
  PIN i_x[62]
    DIRECTION INPUT ;
    USE SIGNAL ;
    PORT
      LAYER M4 ;
        RECT  0 84.672 0.192 84.696 ;
    END
  END i_x[62]
  PIN i_x[63]
    DIRECTION INPUT ;
    USE SIGNAL ;
    PORT
      LAYER M4 ;
        RECT  0 85.056 0.192 85.08 ;
    END
  END i_x[63]
  PIN i_x[64]
    DIRECTION INPUT ;
    USE SIGNAL ;
    PORT
      LAYER M4 ;
        RECT  0 85.44 0.192 85.464 ;
    END
  END i_x[64]
  PIN i_x[65]
    DIRECTION INPUT ;
    USE SIGNAL ;
    PORT
      LAYER M4 ;
        RECT  0 85.824 0.192 85.848 ;
    END
  END i_x[65]
  PIN i_x[66]
    DIRECTION INPUT ;
    USE SIGNAL ;
    PORT
      LAYER M4 ;
        RECT  0 86.208 0.192 86.232 ;
    END
  END i_x[66]
  PIN i_x[67]
    DIRECTION INPUT ;
    USE SIGNAL ;
    PORT
      LAYER M4 ;
        RECT  0 86.592 0.192 86.616 ;
    END
  END i_x[67]
  PIN i_x[68]
    DIRECTION INPUT ;
    USE SIGNAL ;
    PORT
      LAYER M4 ;
        RECT  0 86.976 0.192 87 ;
    END
  END i_x[68]
  PIN i_x[69]
    DIRECTION INPUT ;
    USE SIGNAL ;
    PORT
      LAYER M4 ;
        RECT  0 87.36 0.192 87.384 ;
    END
  END i_x[69]
  PIN i_x[6]
    DIRECTION INPUT ;
    USE SIGNAL ;
    PORT
      LAYER M4 ;
        RECT  0 63.168 0.192 63.192 ;
    END
  END i_x[6]
  PIN i_x[70]
    DIRECTION INPUT ;
    USE SIGNAL ;
    PORT
      LAYER M4 ;
        RECT  0 87.744 0.192 87.768 ;
    END
  END i_x[70]
  PIN i_x[71]
    DIRECTION INPUT ;
    USE SIGNAL ;
    PORT
      LAYER M4 ;
        RECT  0 88.128 0.192 88.152 ;
    END
  END i_x[71]
  PIN i_x[72]
    DIRECTION INPUT ;
    USE SIGNAL ;
    PORT
      LAYER M4 ;
        RECT  0 88.512 0.192 88.536 ;
    END
  END i_x[72]
  PIN i_x[73]
    DIRECTION INPUT ;
    USE SIGNAL ;
    PORT
      LAYER M4 ;
        RECT  0 88.896 0.192 88.92 ;
    END
  END i_x[73]
  PIN i_x[74]
    DIRECTION INPUT ;
    USE SIGNAL ;
    PORT
      LAYER M4 ;
        RECT  0 89.28 0.192 89.304 ;
    END
  END i_x[74]
  PIN i_x[75]
    DIRECTION INPUT ;
    USE SIGNAL ;
    PORT
      LAYER M4 ;
        RECT  0 89.664 0.192 89.688 ;
    END
  END i_x[75]
  PIN i_x[76]
    DIRECTION INPUT ;
    USE SIGNAL ;
    PORT
      LAYER M4 ;
        RECT  0 90.048 0.192 90.072 ;
    END
  END i_x[76]
  PIN i_x[77]
    DIRECTION INPUT ;
    USE SIGNAL ;
    PORT
      LAYER M4 ;
        RECT  0 90.432 0.192 90.456 ;
    END
  END i_x[77]
  PIN i_x[78]
    DIRECTION INPUT ;
    USE SIGNAL ;
    PORT
      LAYER M4 ;
        RECT  0 90.816 0.192 90.84 ;
    END
  END i_x[78]
  PIN i_x[79]
    DIRECTION INPUT ;
    USE SIGNAL ;
    PORT
      LAYER M4 ;
        RECT  0 91.2 0.192 91.224 ;
    END
  END i_x[79]
  PIN i_x[7]
    DIRECTION INPUT ;
    USE SIGNAL ;
    PORT
      LAYER M4 ;
        RECT  0 63.552 0.192 63.576 ;
    END
  END i_x[7]
  PIN i_x[80]
    DIRECTION INPUT ;
    USE SIGNAL ;
    PORT
      LAYER M4 ;
        RECT  0 91.584 0.192 91.608 ;
    END
  END i_x[80]
  PIN i_x[81]
    DIRECTION INPUT ;
    USE SIGNAL ;
    PORT
      LAYER M4 ;
        RECT  0 91.968 0.192 91.992 ;
    END
  END i_x[81]
  PIN i_x[82]
    DIRECTION INPUT ;
    USE SIGNAL ;
    PORT
      LAYER M4 ;
        RECT  0 92.352 0.192 92.376 ;
    END
  END i_x[82]
  PIN i_x[83]
    DIRECTION INPUT ;
    USE SIGNAL ;
    PORT
      LAYER M4 ;
        RECT  0 92.736 0.192 92.76 ;
    END
  END i_x[83]
  PIN i_x[84]
    DIRECTION INPUT ;
    USE SIGNAL ;
    PORT
      LAYER M4 ;
        RECT  0 93.12 0.192 93.144 ;
    END
  END i_x[84]
  PIN i_x[85]
    DIRECTION INPUT ;
    USE SIGNAL ;
    PORT
      LAYER M4 ;
        RECT  0 93.504 0.192 93.528 ;
    END
  END i_x[85]
  PIN i_x[86]
    DIRECTION INPUT ;
    USE SIGNAL ;
    PORT
      LAYER M4 ;
        RECT  0 93.888 0.192 93.912 ;
    END
  END i_x[86]
  PIN i_x[87]
    DIRECTION INPUT ;
    USE SIGNAL ;
    PORT
      LAYER M4 ;
        RECT  0 94.272 0.192 94.296 ;
    END
  END i_x[87]
  PIN i_x[88]
    DIRECTION INPUT ;
    USE SIGNAL ;
    PORT
      LAYER M4 ;
        RECT  0 94.656 0.192 94.68 ;
    END
  END i_x[88]
  PIN i_x[89]
    DIRECTION INPUT ;
    USE SIGNAL ;
    PORT
      LAYER M4 ;
        RECT  0 95.04 0.192 95.064 ;
    END
  END i_x[89]
  PIN i_x[8]
    DIRECTION INPUT ;
    USE SIGNAL ;
    PORT
      LAYER M4 ;
        RECT  0 63.936 0.192 63.96 ;
    END
  END i_x[8]
  PIN i_x[90]
    DIRECTION INPUT ;
    USE SIGNAL ;
    PORT
      LAYER M4 ;
        RECT  0 95.424 0.192 95.448 ;
    END
  END i_x[90]
  PIN i_x[91]
    DIRECTION INPUT ;
    USE SIGNAL ;
    PORT
      LAYER M4 ;
        RECT  0 95.808 0.192 95.832 ;
    END
  END i_x[91]
  PIN i_x[92]
    DIRECTION INPUT ;
    USE SIGNAL ;
    PORT
      LAYER M4 ;
        RECT  0 96.192 0.192 96.216 ;
    END
  END i_x[92]
  PIN i_x[93]
    DIRECTION INPUT ;
    USE SIGNAL ;
    PORT
      LAYER M4 ;
        RECT  0 96.576 0.192 96.6 ;
    END
  END i_x[93]
  PIN i_x[94]
    DIRECTION INPUT ;
    USE SIGNAL ;
    PORT
      LAYER M4 ;
        RECT  0 96.96 0.192 96.984 ;
    END
  END i_x[94]
  PIN i_x[95]
    DIRECTION INPUT ;
    USE SIGNAL ;
    PORT
      LAYER M4 ;
        RECT  0 97.344 0.192 97.368 ;
    END
  END i_x[95]
  PIN i_x[96]
    DIRECTION INPUT ;
    USE SIGNAL ;
    PORT
      LAYER M4 ;
        RECT  0 97.728 0.192 97.752 ;
    END
  END i_x[96]
  PIN i_x[97]
    DIRECTION INPUT ;
    USE SIGNAL ;
    PORT
      LAYER M4 ;
        RECT  0 98.112 0.192 98.136 ;
    END
  END i_x[97]
  PIN i_x[98]
    DIRECTION INPUT ;
    USE SIGNAL ;
    PORT
      LAYER M4 ;
        RECT  0 98.496 0.192 98.52 ;
    END
  END i_x[98]
  PIN i_x[99]
    DIRECTION INPUT ;
    USE SIGNAL ;
    PORT
      LAYER M4 ;
        RECT  0 98.88 0.192 98.904 ;
    END
  END i_x[99]
  PIN i_x[9]
    DIRECTION INPUT ;
    USE SIGNAL ;
    PORT
      LAYER M4 ;
        RECT  0 64.32 0.192 64.344 ;
    END
  END i_x[9]
  PIN otag[0]
    DIRECTION OUTPUT ;
    USE SIGNAL ;
    PORT
      LAYER M4 ;
        RECT  155.328 109.728 155.52 109.752 ;
    END
  END otag[0]
  PIN otag[10]
    DIRECTION OUTPUT ;
    USE SIGNAL ;
    PORT
      LAYER M4 ;
        RECT  155.328 111.648 155.52 111.672 ;
    END
  END otag[10]
  PIN otag[11]
    DIRECTION OUTPUT ;
    USE SIGNAL ;
    PORT
      LAYER M4 ;
        RECT  155.328 111.84 155.52 111.864 ;
    END
  END otag[11]
  PIN otag[12]
    DIRECTION OUTPUT ;
    USE SIGNAL ;
    PORT
      LAYER M4 ;
        RECT  155.328 112.032 155.52 112.056 ;
    END
  END otag[12]
  PIN otag[13]
    DIRECTION OUTPUT ;
    USE SIGNAL ;
    PORT
      LAYER M4 ;
        RECT  155.328 112.224 155.52 112.248 ;
    END
  END otag[13]
  PIN otag[14]
    DIRECTION OUTPUT ;
    USE SIGNAL ;
    PORT
      LAYER M4 ;
        RECT  155.328 112.416 155.52 112.44 ;
    END
  END otag[14]
  PIN otag[15]
    DIRECTION OUTPUT ;
    USE SIGNAL ;
    PORT
      LAYER M4 ;
        RECT  155.328 112.608 155.52 112.632 ;
    END
  END otag[15]
  PIN otag[1]
    DIRECTION OUTPUT ;
    USE SIGNAL ;
    PORT
      LAYER M4 ;
        RECT  155.328 109.92 155.52 109.944 ;
    END
  END otag[1]
  PIN otag[2]
    DIRECTION OUTPUT ;
    USE SIGNAL ;
    PORT
      LAYER M4 ;
        RECT  155.328 110.112 155.52 110.136 ;
    END
  END otag[2]
  PIN otag[3]
    DIRECTION OUTPUT ;
    USE SIGNAL ;
    PORT
      LAYER M4 ;
        RECT  155.328 110.304 155.52 110.328 ;
    END
  END otag[3]
  PIN otag[4]
    DIRECTION OUTPUT ;
    USE SIGNAL ;
    PORT
      LAYER M4 ;
        RECT  155.328 110.496 155.52 110.52 ;
    END
  END otag[4]
  PIN otag[5]
    DIRECTION OUTPUT ;
    USE SIGNAL ;
    PORT
      LAYER M4 ;
        RECT  155.328 110.688 155.52 110.712 ;
    END
  END otag[5]
  PIN otag[6]
    DIRECTION OUTPUT ;
    USE SIGNAL ;
    PORT
      LAYER M4 ;
        RECT  155.328 110.88 155.52 110.904 ;
    END
  END otag[6]
  PIN otag[7]
    DIRECTION OUTPUT ;
    USE SIGNAL ;
    PORT
      LAYER M4 ;
        RECT  155.328 111.072 155.52 111.096 ;
    END
  END otag[7]
  PIN otag[8]
    DIRECTION OUTPUT ;
    USE SIGNAL ;
    PORT
      LAYER M4 ;
        RECT  155.328 111.264 155.52 111.288 ;
    END
  END otag[8]
  PIN otag[9]
    DIRECTION OUTPUT ;
    USE SIGNAL ;
    PORT
      LAYER M4 ;
        RECT  155.328 111.456 155.52 111.48 ;
    END
  END otag[9]
  PIN ov
    DIRECTION OUTPUT ;
    USE SIGNAL ;
    PORT
      LAYER M4 ;
        RECT  155.328 103.2 155.52 103.224 ;
    END
  END ov
  PIN rst_a
    DIRECTION INPUT ;
    USE SIGNAL ;
    PORT
      LAYER M5 ;
        RECT  78.24 215.808 78.264 216 ;
    END
  END rst_a
  PIN y[0]
    DIRECTION OUTPUT ;
    USE SIGNAL ;
    PORT
      LAYER M4 ;
        RECT  155.328 103.584 155.52 103.608 ;
    END
  END y[0]
  PIN y[10]
    DIRECTION OUTPUT ;
    USE SIGNAL ;
    PORT
      LAYER M4 ;
        RECT  155.328 105.504 155.52 105.528 ;
    END
  END y[10]
  PIN y[11]
    DIRECTION OUTPUT ;
    USE SIGNAL ;
    PORT
      LAYER M4 ;
        RECT  155.328 105.696 155.52 105.72 ;
    END
  END y[11]
  PIN y[12]
    DIRECTION OUTPUT ;
    USE SIGNAL ;
    PORT
      LAYER M4 ;
        RECT  155.328 105.888 155.52 105.912 ;
    END
  END y[12]
  PIN y[13]
    DIRECTION OUTPUT ;
    USE SIGNAL ;
    PORT
      LAYER M4 ;
        RECT  155.328 106.08 155.52 106.104 ;
    END
  END y[13]
  PIN y[14]
    DIRECTION OUTPUT ;
    USE SIGNAL ;
    PORT
      LAYER M4 ;
        RECT  155.328 106.272 155.52 106.296 ;
    END
  END y[14]
  PIN y[15]
    DIRECTION OUTPUT ;
    USE SIGNAL ;
    PORT
      LAYER M4 ;
        RECT  155.328 106.464 155.52 106.488 ;
    END
  END y[15]
  PIN y[16]
    DIRECTION OUTPUT ;
    USE SIGNAL ;
    PORT
      LAYER M4 ;
        RECT  155.328 106.656 155.52 106.68 ;
    END
  END y[16]
  PIN y[17]
    DIRECTION OUTPUT ;
    USE SIGNAL ;
    PORT
      LAYER M4 ;
        RECT  155.328 106.848 155.52 106.872 ;
    END
  END y[17]
  PIN y[18]
    DIRECTION OUTPUT ;
    USE SIGNAL ;
    PORT
      LAYER M4 ;
        RECT  155.328 107.04 155.52 107.064 ;
    END
  END y[18]
  PIN y[19]
    DIRECTION OUTPUT ;
    USE SIGNAL ;
    PORT
      LAYER M4 ;
        RECT  155.328 107.232 155.52 107.256 ;
    END
  END y[19]
  PIN y[1]
    DIRECTION OUTPUT ;
    USE SIGNAL ;
    PORT
      LAYER M4 ;
        RECT  155.328 103.776 155.52 103.8 ;
    END
  END y[1]
  PIN y[20]
    DIRECTION OUTPUT ;
    USE SIGNAL ;
    PORT
      LAYER M4 ;
        RECT  155.328 107.424 155.52 107.448 ;
    END
  END y[20]
  PIN y[21]
    DIRECTION OUTPUT ;
    USE SIGNAL ;
    PORT
      LAYER M4 ;
        RECT  155.328 107.616 155.52 107.64 ;
    END
  END y[21]
  PIN y[22]
    DIRECTION OUTPUT ;
    USE SIGNAL ;
    PORT
      LAYER M4 ;
        RECT  155.328 107.808 155.52 107.832 ;
    END
  END y[22]
  PIN y[23]
    DIRECTION OUTPUT ;
    USE SIGNAL ;
    PORT
      LAYER M4 ;
        RECT  155.328 108 155.52 108.024 ;
    END
  END y[23]
  PIN y[24]
    DIRECTION OUTPUT ;
    USE SIGNAL ;
    PORT
      LAYER M4 ;
        RECT  155.328 108.192 155.52 108.216 ;
    END
  END y[24]
  PIN y[25]
    DIRECTION OUTPUT ;
    USE SIGNAL ;
    PORT
      LAYER M4 ;
        RECT  155.328 108.384 155.52 108.408 ;
    END
  END y[25]
  PIN y[26]
    DIRECTION OUTPUT ;
    USE SIGNAL ;
    PORT
      LAYER M4 ;
        RECT  155.328 108.576 155.52 108.6 ;
    END
  END y[26]
  PIN y[27]
    DIRECTION OUTPUT ;
    USE SIGNAL ;
    PORT
      LAYER M4 ;
        RECT  155.328 108.768 155.52 108.792 ;
    END
  END y[27]
  PIN y[28]
    DIRECTION OUTPUT ;
    USE SIGNAL ;
    PORT
      LAYER M4 ;
        RECT  155.328 108.96 155.52 108.984 ;
    END
  END y[28]
  PIN y[29]
    DIRECTION OUTPUT ;
    USE SIGNAL ;
    PORT
      LAYER M4 ;
        RECT  155.328 109.152 155.52 109.176 ;
    END
  END y[29]
  PIN y[2]
    DIRECTION OUTPUT ;
    USE SIGNAL ;
    PORT
      LAYER M4 ;
        RECT  155.328 103.968 155.52 103.992 ;
    END
  END y[2]
  PIN y[30]
    DIRECTION OUTPUT ;
    USE SIGNAL ;
    PORT
      LAYER M4 ;
        RECT  155.328 109.344 155.52 109.368 ;
    END
  END y[30]
  PIN y[31]
    DIRECTION OUTPUT ;
    USE SIGNAL ;
    PORT
      LAYER M4 ;
        RECT  155.328 109.536 155.52 109.56 ;
    END
  END y[31]
  PIN y[3]
    DIRECTION OUTPUT ;
    USE SIGNAL ;
    PORT
      LAYER M4 ;
        RECT  155.328 104.16 155.52 104.184 ;
    END
  END y[3]
  PIN y[4]
    DIRECTION OUTPUT ;
    USE SIGNAL ;
    PORT
      LAYER M4 ;
        RECT  155.328 104.352 155.52 104.376 ;
    END
  END y[4]
  PIN y[5]
    DIRECTION OUTPUT ;
    USE SIGNAL ;
    PORT
      LAYER M4 ;
        RECT  155.328 104.544 155.52 104.568 ;
    END
  END y[5]
  PIN y[6]
    DIRECTION OUTPUT ;
    USE SIGNAL ;
    PORT
      LAYER M4 ;
        RECT  155.328 104.736 155.52 104.76 ;
    END
  END y[6]
  PIN y[7]
    DIRECTION OUTPUT ;
    USE SIGNAL ;
    PORT
      LAYER M4 ;
        RECT  155.328 104.928 155.52 104.952 ;
    END
  END y[7]
  PIN y[8]
    DIRECTION OUTPUT ;
    USE SIGNAL ;
    PORT
      LAYER M4 ;
        RECT  155.328 105.12 155.52 105.144 ;
    END
  END y[8]
  PIN y[9]
    DIRECTION OUTPUT ;
    USE SIGNAL ;
    PORT
      LAYER M4 ;
        RECT  155.328 105.312 155.52 105.336 ;
    END
  END y[9]
  PIN VDD
    DIRECTION INOUT ;
    USE POWER ;
    PORT
      LAYER M6 ;
        RECT  0.468 208.52 155.052 208.808 ;
        RECT  0.468 197.72 155.052 198.008 ;
        RECT  0.468 186.92 155.052 187.208 ;
        RECT  0.468 176.12 155.052 176.408 ;
        RECT  0.468 165.32 155.052 165.608 ;
        RECT  0.468 154.52 155.052 154.808 ;
        RECT  0.468 143.72 155.052 144.008 ;
        RECT  0.468 132.92 155.052 133.208 ;
        RECT  0.468 122.12 155.052 122.408 ;
        RECT  0.468 111.32 155.052 111.608 ;
        RECT  0.468 100.52 155.052 100.808 ;
        RECT  0.468 89.72 155.052 90.008 ;
        RECT  0.468 78.92 155.052 79.208 ;
        RECT  0.468 68.12 155.052 68.408 ;
        RECT  0.468 57.32 155.052 57.608 ;
        RECT  0.468 46.52 155.052 46.808 ;
        RECT  0.468 35.72 155.052 36.008 ;
        RECT  0.468 24.92 155.052 25.208 ;
        RECT  0.468 14.12 155.052 14.408 ;
        RECT  0.468 3.32 155.052 3.608 ;
        RECT  0.468 215.604 155.052 215.892 ;
        RECT  0.468 0.108 155.052 0.396 ;
    END
  END VDD
  PIN VSS
    DIRECTION INOUT ;
    USE GROUND ;
    PORT
      LAYER M6 ;
        RECT  0.468 208.136 155.052 208.424 ;
        RECT  0.468 197.336 155.052 197.624 ;
        RECT  0.468 186.536 155.052 186.824 ;
        RECT  0.468 175.736 155.052 176.024 ;
        RECT  0.468 164.936 155.052 165.224 ;
        RECT  0.468 154.136 155.052 154.424 ;
        RECT  0.468 143.336 155.052 143.624 ;
        RECT  0.468 132.536 155.052 132.824 ;
        RECT  0.468 121.736 155.052 122.024 ;
        RECT  0.468 110.936 155.052 111.224 ;
        RECT  0.468 100.136 155.052 100.424 ;
        RECT  0.468 89.336 155.052 89.624 ;
        RECT  0.468 78.536 155.052 78.824 ;
        RECT  0.468 67.736 155.052 68.024 ;
        RECT  0.468 56.936 155.052 57.224 ;
        RECT  0.468 46.136 155.052 46.424 ;
        RECT  0.468 35.336 155.052 35.624 ;
        RECT  0.468 24.536 155.052 24.824 ;
        RECT  0.468 13.736 155.052 14.024 ;
        RECT  0.468 2.936 155.052 3.224 ;
        RECT  0.66 215.22 154.86 215.508 ;
        RECT  0.66 0.492 154.86 0.78 ;
    END
  END VSS
  OBS
    LAYER RVTN ;
     RECT  0 0.108 155.52 216 ;
    LAYER RVTP ;
     RECT  0 0.108 155.52 216 ;
    LAYER M1 ;
     RECT  0 0.108 155.52 216 ;
    LAYER M2 ;
     RECT  0 0.108 155.52 216 ;
    LAYER M3 ;
     RECT  0 0.108 155.52 216 ;
    LAYER M4 ;
     RECT  0 0.108 155.52 216 ;
    LAYER M5 ;
     RECT  0 0.108 155.52 216 ;
    LAYER M6 ;
     RECT  0 0.108 155.52 216 ;
    LAYER M7 ;
     RECT  0 0.108 155.52 216 ;
  END
END ot_hbm_accel_smh_tcc
END LIBRARY
